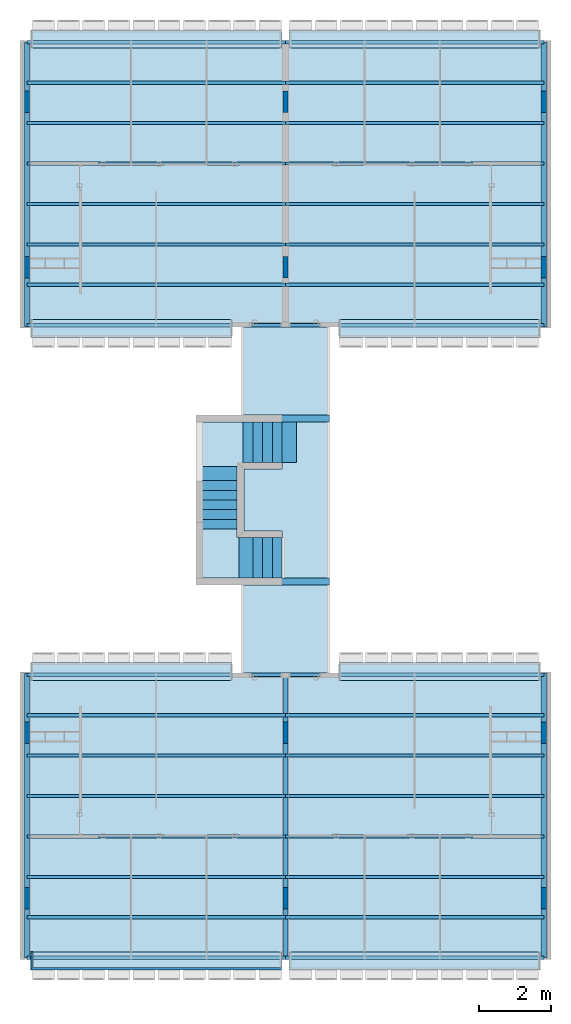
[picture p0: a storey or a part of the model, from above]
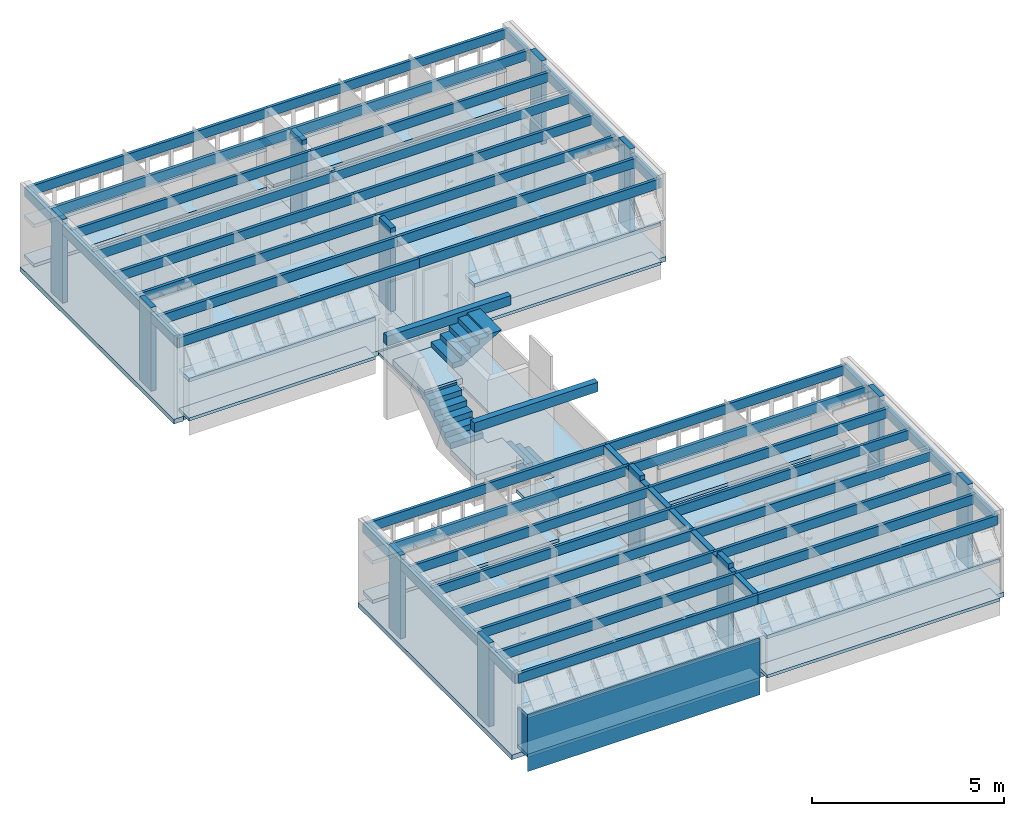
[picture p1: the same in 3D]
Properties of the parts of a building model (IFC2X3), part 1 of 3

# File
Description: ViewDefinition [CoordinationView_V2.0], ExchangeRequirement [Architecture], Option [IfcExportBaseQuantities: Off], Option [IfcExportElementOnOffAndFrozenLayers: On], Option [IfcExplodeExternalReferences: Off], Option [IfcTesselateBSplineCurvesAndSurfaces: Off], Option [IfcExportSweptSolidAsBRep: Off], Option [IfcExportProfileCenterOfGravity: Off], Option [IfcExportMultiPlyElementsAsAggregated: Off], Option [IfcExportTesselation: 0.000000], Option [IfcCreateUniqueGuidForBlocks: On], Option [IfcCreateUniqueGuidForXrefs: On]
File name: C:\\Users\\Marcelo\\Documents\\FAU\\_LabBIM 2021 2022\\_Servidor Modelos FAU\\Tadashi-Cecap-Archicad\\CECAP-PMR R06 IFC2X3 pav2 bricscad.ifc
Time: 2024-07-12T12:13:49
Author: Undefined
Organization: Undefined
Written by: BricsCAD BIM 24.2.06
Made in: BricsCAD BIM 24.2.06
Authorization: Undefined

# IfcSite, Site
RefLatitude: -23, -32, 0, 0; RefLongitude: -46, -38, 0, 0; RefElevation: 0 mm

# IfcBuilding, Construção
ElevationOfRefHeight: 0 mm; ElevationOfTerrain: 0 mm

# IfcBuildingStorey, Segundo Pavimento
In: Construção
Elevation: 2650 mm

# IfcSpace: CIRCULAÇÃO (2)
In: Segundo Pavimento
AC_Equantity_Selo_de_Zona_01_25 - Perímetro dos Vãos: 0; Largura Combinada das Janelas: 0; Nível do Piso: 0; Espessura do Subpiso: 0; Tamanho de Fonte para Texto de Detalhe (modelo): 300
AC_Pset_RenovationAndPhasing - Renovation Status: Existing
ArchiCADQuantities - Elevação à Origem do Projeto: 2650; Elevação ao 1º Nível de Referência: 2650; Elevação ao 2º Nível de Referência: 2650; Elevação ao Nível do Mar: 2650; Elevação ao Piso: 0; Afastamento da Origem: 0; Elevação da Base Ao Primeiro Nível de Referência: 2650; Elevação da Base Ao Piso de Origem: 0; Elevação da Base À Cota Zero: 2650; Elevação da Base Ao Nível do Mar: 2650; Elevação da Base Ao Segundo Nível de Referência: 2650; Afastamento do Topo: 0; Número de Janelas: 0; Número de Pilares: 0; Perímetro Furos da Planta: 0; Nível Base: 0; Número de Luminárias: 0; Número de Objetos: 0; Área de Superfície das Janelas: 0; Largura Janelas: 0; Espessura de Pavimento: 0; Redução de área: 1; Extrair Área da Base do Pilar: 0; Extrair Área da Trama: 0; Área Baixa Extraída: 0; Extrair Área da Base da Parede: 0; Área Total Extraída: 0; Inserção da Parede no Lado Posterior da Área de Superfície: 0; Inserção da Parede no Lado da Área de Superfície: 0; Inserção da Parede na Área da Superfície do Topo: 0; Área Extraída da Parede Cortina: 0
BaseQuantities - FinishFloorHeight: 0
ILUMINAÇÃO E VENTILAÇÃO (Expressão) - Área das Aberturas Projetada: 0; Atende: Atende; Não Atende: Não Atende
REVESTIMENTO DE PAREDE POR ZONA (Expressão) - Número de Linhas: 10; DImensão 1: 0; Dimensão 2: 0; Largura do Rejunte: 10; Altura do Revestimento: 100
RODAPÉ (Expressão) - Comprimento da Barra (m): 2.4; Custo da Barra: 0; Estimativa de Custo: 0
Name | LongName | Classification | Perímetro = Perímetro Útil = Perímetro Útil da Zona = Perímetro Bruto Zona = GrossPerimeter = NetPerimeter | Comprimento das Paredes Perímetro = Perímetro Paredes | Largura Combinada das Portas = Largura Portas | Altura-2 = Altura = Elevação do Topo Ao Piso de Origem = Height = FinishCeilingHeight = ClearHeight | Área = Área da Superfície do Topo (Líquida) = Área da Superfície da Base (Líquida) = Área Calculada = Área Medida = Área Líquida Medida = Área Reduzida = GrossFloorArea = NetFloorArea = SpaceNetFloorAreaBOMA = SpaceUsableFloorAreaBOMA = GrossCeilingArea = NetCeilingArea | Volume (Líquido) = GrossVolume = NetVolume | Elevação do Topo ao Primeiro Nível de Referência = Elevação do Topo À Cota Zero = Elevação do Topo Ao Nível do Mar = Elevação do Topo Ao Segundo Nível de Referência | Área da Superfície da Borda (Líquida) | Número de Portas | Número de Vigas | Número de Itens de Paredes | Área de Superfície das Portas | Área de Superfície das Paredes = NetWallArea | Número dos Cantos Côncavos | Número de Cantos | GrossWallArea | ID Dinâmico por Classificação | Zona - Número de Azulejos Necessários | Quantidade de Barras | Estimativa de Rodapé (ml)
33 | CORREDOR | Zoneamento (Classificação ARCHICAD); 4A 16 04 01 Corredor (NBR 15965-6 4A) | 28680 | 26812.9 | 3600 | 2650 | 20.0698 | 53.185 | 5300 | 76.002 | 4 | 6 | 23 | 7.56 | 34.421 | 10 | 24 | 41.981 | Zoneamento -032 | 25080 | 10 | 23212.9
34 | ESCADA | Zoneamento (Classificação ARCHICAD); 4A 16 01 04 07 Escada de Uso Comum (NBR 15965-6 4A) | 15630 | 9050 | 0 | 5300 | 7.0315 | 37.2669 | 7950 | 41.4195 | 0 | 2 | 6 | 0 | 23.0336 | 2 | 8 | 23.0336 | Zoneamento -031 | 15630 | 4 | 9050

# IfcSpace: ÁREA PRIVATIVA APTO 05 (7)
In: Segundo Pavimento
AC_Equantity_Selo_de_Zona_01_25 - Perímetro dos Vãos: 0; Nível do Piso: 0; Espessura do Subpiso: 0; Altura-2: 2650; Tamanho de Fonte para Texto de Detalhe (modelo): 300
AC_Pset_RenovationAndPhasing - Renovation Status: Existing
ArchiCADQuantities - Altura: 2650; Elevação à Origem do Projeto: 2650; Elevação ao 1º Nível de Referência: 2650; Elevação ao 2º Nível de Referência: 2650; Elevação ao Nível do Mar: 2650; Elevação ao Piso: 0; Afastamento da Origem: 0; Elevação do Topo ao Primeiro Nível de Referência: 5300; Elevação do Topo Ao Piso de Origem: 2650; Elevação do Topo À Cota Zero: 5300; Elevação do Topo Ao Nível do Mar: 5300; Elevação do Topo Ao Segundo Nível de Referência: 5300; Elevação da Base Ao Primeiro Nível de Referência: 2650; Elevação da Base Ao Piso de Origem: 0; Elevação da Base À Cota Zero: 2650; Elevação da Base Ao Nível do Mar: 2650; Elevação da Base Ao Segundo Nível de Referência: 2650; Afastamento do Topo: 0; Número de Janelas: 0; Número de Pilares: 0; Perímetro Furos da Planta: 0; Nível Base: 0; Número de Luminárias: 0; Número de Objetos: 0; Área de Superfície das Janelas: 0; Largura Janelas: 0; Espessura de Pavimento: 0; Redução de área: 1; Extrair Área da Base do Pilar: 0; Extrair Área da Trama: 0; Área Baixa Extraída: 0; Extrair Área da Base da Parede: 0; Número dos Cantos Côncavos: 0; Número de Cantos: 4; Área Total Extraída: 0; Inserção da Parede no Lado Posterior da Área de Superfície: 0; Inserção da Parede no Lado da Área de Superfície: 0; Inserção da Parede na Área da Superfície do Topo: 0; Área Extraída da Parede Cortina: 0
BaseQuantities - Height: 2650; FinishCeilingHeight: 2650; FinishFloorHeight: 0; ClearHeight: 2650
ILUMINAÇÃO E VENTILAÇÃO (Expressão) - Área das Aberturas Projetada: 0; Atende: Atende; Não Atende: Não Atende
REVESTIMENTO DE PAREDE POR ZONA (Expressão) - Número de Linhas: 10; DImensão 1: 0; Dimensão 2: 0; Largura do Rejunte: 10; Altura do Revestimento: 100
RODAPÉ (Expressão) - Comprimento da Barra (m): 2.4; Custo da Barra: 0; Estimativa de Custo: 0
Name | LongName | Classification | Perímetro = Perímetro Útil = Perímetro Útil da Zona = Perímetro Bruto Zona = GrossPerimeter = NetPerimeter | Comprimento das Paredes Perímetro = Perímetro Paredes | Largura Combinada das Portas | Largura Combinada das Janelas | Área = Área da Superfície do Topo (Líquida) = Área da Superfície da Base (Líquida) = Área Calculada = Área Medida = Área Líquida Medida = Área Reduzida = GrossFloorArea = NetFloorArea = SpaceNetFloorAreaBOMA = SpaceUsableFloorAreaBOMA = GrossCeilingArea = NetCeilingArea | Volume (Líquido) = GrossVolume = NetVolume | Área da Superfície da Borda (Líquida) | Número de Portas | Número de Vigas | Número de Itens de Paredes | Área de Superfície das Portas | Área de Superfície das Paredes = NetWallArea | Largura Portas | GrossWallArea | ID Dinâmico por Classificação | Zona - Número de Azulejos Necessários | Quantidade de Barras | Estimativa de Rodapé (ml)
17 | LAVANDERIA | Zoneamento (Classificação ARCHICAD); 4A 19 04 04 Lavanderia (NBR 15965-6 4A) | 5940 | 3510 | 0 | 0 | 2.187 | 5.79555 | 15.741 | 0 | 2 | 3 | 0 | 9.09455 | 0 | 9.09455 | Zoneamento -025 | 5940 | 2 | 3510
09 | SALA | Zoneamento (Classificação ARCHICAD); 4A 19 01 07 Sala de Estar (NBR 15965-6 4A) | 15959.6 | 9809.78 | 710 | 2040 | 15.6592 | 41.497 | 42.2928 | 1 | 5 | 5 | 1.89 | 21.4728 | 900 | 23.3628 | Zoneamento -024 | 15060 | 4 | 8909.78
31 | QUARTO | Zoneamento (Classificação ARCHICAD); 4A 19 01 01 Dormitório (NBR 15965-6 4A) | 11010.2 | 8850.18 | 0 | 2080 | 7.12419 | 18.8791 | 29.177 | 0 | 4 | 2 | 0 | 16.794 | 0 | 16.794 | Zoneamento -028 | 11010 | 4 | 8850.18
13 | WC | Zoneamento (Classificação ARCHICAD); 4A 19 04 07 Banheiro residencial (NBR 15965-6 4A) | 7859.56 | 7859.56 | 710 | 0 | 3.4827 | 9.22916 | 20.8278 | 1 | 3 | 4 | 1.491 | 17.6449 | 710 | 19.1359 | Zoneamento -029 | 7150 | 3 | 7149.56
05 | COZINHA | Zoneamento (Classificação ARCHICAD); 4A 19 01 25 Cozinha (NBR 15965-6 4A) | 13079.6 | 9809.78 | 710 | 2040 | 9.17955 | 24.3258 | 34.6608 | 1 | 5 | 3 | 1.491 | 17.572 | 710 | 19.063 | Zoneamento -026 | 12370 | 4 | 9099.78
27 | QUARTO | Zoneamento (Classificação ARCHICAD); 4A 19 01 01 Dormitório (NBR 15965-6 4A) | 10970.4 | 8830.36 | 0 | 2060 | 7.05588 | 18.6981 | 29.0715 | 0 | 4 | 2 | 0 | 16.8413 | 0 | 16.8413 | Zoneamento -027 | 10970 | 4 | 8830.36
23 | QUARTO | Zoneamento (Classificação ARCHICAD); 4A 19 01 01 Dormitório (NBR 15965-6 4A) | 12310.4 | 11330.4 | 0 | 2780 | 9.38311 | 24.8652 | 32.6227 | 0 | 3 | 2 | 0 | 16.6677 | 0 | 16.6677 | Zoneamento -030 | 12311 | 5 | 11330.4

# IfcSpace: ÁREA PRIVATIVA APTO 06 (7)
In: Segundo Pavimento
AC_Equantity_Selo_de_Zona_01_25 - Perímetro dos Vãos: 0; Nível do Piso: 0; Espessura do Subpiso: 0; Altura-2: 2650; Tamanho de Fonte para Texto de Detalhe (modelo): 300
AC_Pset_RenovationAndPhasing - Renovation Status: Existing
ArchiCADQuantities - Altura: 2650; Elevação à Origem do Projeto: 2650; Elevação ao 1º Nível de Referência: 2650; Elevação ao 2º Nível de Referência: 2650; Elevação ao Nível do Mar: 2650; Elevação ao Piso: 0; Afastamento da Origem: 0; Elevação do Topo ao Primeiro Nível de Referência: 5300; Elevação do Topo Ao Piso de Origem: 2650; Elevação do Topo À Cota Zero: 5300; Elevação do Topo Ao Nível do Mar: 5300; Elevação do Topo Ao Segundo Nível de Referência: 5300; Elevação da Base Ao Primeiro Nível de Referência: 2650; Elevação da Base Ao Piso de Origem: 0; Elevação da Base À Cota Zero: 2650; Elevação da Base Ao Nível do Mar: 2650; Elevação da Base Ao Segundo Nível de Referência: 2650; Afastamento do Topo: 0; Número de Janelas: 0; Número de Pilares: 0; Perímetro Furos da Planta: 0; Nível Base: 0; Número de Luminárias: 0; Número de Objetos: 0; Área de Superfície das Janelas: 0; Largura Janelas: 0; Espessura de Pavimento: 0; Redução de área: 1; Extrair Área da Base do Pilar: 0; Extrair Área da Trama: 0; Área Baixa Extraída: 0; Extrair Área da Base da Parede: 0; Número dos Cantos Côncavos: 0; Número de Cantos: 4; Área Total Extraída: 0; Inserção da Parede no Lado Posterior da Área de Superfície: 0; Inserção da Parede no Lado da Área de Superfície: 0; Inserção da Parede na Área da Superfície do Topo: 0; Área Extraída da Parede Cortina: 0
BaseQuantities - Height: 2650; FinishCeilingHeight: 2650; FinishFloorHeight: 0; ClearHeight: 2650
ILUMINAÇÃO E VENTILAÇÃO (Expressão) - Área das Aberturas Projetada: 0; Atende: Atende; Não Atende: Não Atende
REVESTIMENTO DE PAREDE POR ZONA (Expressão) - Número de Linhas: 10; DImensão 1: 0; Dimensão 2: 0; Largura do Rejunte: 10; Altura do Revestimento: 100
RODAPÉ (Expressão) - Comprimento da Barra (m): 2.4; Custo da Barra: 0; Estimativa de Custo: 0
Name | LongName | Classification | Perímetro = Perímetro Útil = Perímetro Útil da Zona = Perímetro Bruto Zona = GrossPerimeter = NetPerimeter | Comprimento das Paredes Perímetro = Perímetro Paredes | Largura Combinada das Portas | Largura Combinada das Janelas | Área = Área da Superfície do Topo (Líquida) = Área da Superfície da Base (Líquida) = Área Calculada = Área Medida = Área Líquida Medida = Área Reduzida = GrossFloorArea = NetFloorArea = SpaceNetFloorAreaBOMA = SpaceUsableFloorAreaBOMA = GrossCeilingArea = NetCeilingArea | Volume (Líquido) = GrossVolume = NetVolume | Área da Superfície da Borda (Líquida) | Número de Portas | Número de Vigas | Número de Itens de Paredes | Área de Superfície das Portas | Área de Superfície das Paredes = NetWallArea | Largura Portas | GrossWallArea | ID Dinâmico por Classificação | Zona - Número de Azulejos Necessários | Quantidade de Barras | Estimativa de Rodapé (ml)
13 | WC | Zoneamento (Classificação ARCHICAD); 4A 19 04 07 Banheiro residencial (NBR 15965-6 4A) | 7859.56 | 7859.56 | 710 | 0 | 3.4827 | 9.22916 | 20.8278 | 1 | 3 | 4 | 1.491 | 17.6449 | 710 | 19.1359 | Zoneamento -015 | 7150 | 3 | 7149.56
23 | QUARTO | Zoneamento (Classificação ARCHICAD); 4A 19 01 01 Dormitório (NBR 15965-6 4A) | 12310.4 | 11330.4 | 0 | 2780 | 9.38311 | 24.8652 | 32.6227 | 0 | 3 | 2 | 0 | 16.6677 | 0 | 16.6677 | Zoneamento -014 | 12311 | 5 | 11330.4
05 | COZINHA | Zoneamento (Classificação ARCHICAD); 4A 19 01 25 Cozinha (NBR 15965-6 4A) | 13079.6 | 9809.78 | 710 | 2040 | 9.17955 | 24.3258 | 34.6608 | 1 | 5 | 3 | 1.491 | 17.572 | 710 | 19.063 | Zoneamento -016 | 12370 | 4 | 9099.78
09 | SALA | Zoneamento (Classificação ARCHICAD); 4A 19 01 07 Sala de Estar (NBR 15965-6 4A) | 15959.6 | 9809.78 | 710 | 2040 | 15.6592 | 41.497 | 42.2928 | 1 | 5 | 5 | 1.89 | 21.4728 | 900 | 23.3628 | Zoneamento -017 | 15060 | 4 | 8909.78
17 | LAVANDERIA | Zoneamento (Classificação ARCHICAD); 4A 19 04 04 Lavanderia (NBR 15965-6 4A) | 5940 | 3510 | 0 | 0 | 2.187 | 5.79555 | 15.741 | 0 | 2 | 3 | 0 | 9.09455 | 0 | 9.09455 | Zoneamento -035 | 5940 | 2 | 3510
27 | QUARTO | Zoneamento (Classificação ARCHICAD); 4A 19 01 01 Dormitório (NBR 15965-6 4A) | 10970.4 | 8830.36 | 0 | 2060 | 7.05588 | 18.6981 | 29.0715 | 0 | 4 | 2 | 0 | 16.8413 | 0 | 16.8413 | Zoneamento -034 | 10970 | 4 | 8830.36
31 | QUARTO | Zoneamento (Classificação ARCHICAD); 4A 19 01 01 Dormitório (NBR 15965-6 4A) | 11010.2 | 8850.18 | 0 | 2080 | 7.12419 | 18.8791 | 29.177 | 0 | 4 | 2 | 0 | 16.794 | 0 | 16.794 | Zoneamento -033 | 11010 | 4 | 8850.18

# IfcSpace: ÁREA PRIVATIVA APTO 07 (7)
In: Segundo Pavimento
AC_Equantity_Selo_de_Zona_01_25 - Perímetro dos Vãos: 0; Nível do Piso: 0; Espessura do Subpiso: 0; Altura-2: 2650; Tamanho de Fonte para Texto de Detalhe (modelo): 300
AC_Pset_RenovationAndPhasing - Renovation Status: Existing
ArchiCADQuantities - Altura: 2650; Elevação à Origem do Projeto: 2650; Elevação ao 1º Nível de Referência: 2650; Elevação ao 2º Nível de Referência: 2650; Elevação ao Nível do Mar: 2650; Elevação ao Piso: 0; Afastamento da Origem: 0; Elevação do Topo ao Primeiro Nível de Referência: 5300; Elevação do Topo Ao Piso de Origem: 2650; Elevação do Topo À Cota Zero: 5300; Elevação do Topo Ao Nível do Mar: 5300; Elevação do Topo Ao Segundo Nível de Referência: 5300; Elevação da Base Ao Primeiro Nível de Referência: 2650; Elevação da Base Ao Piso de Origem: 0; Elevação da Base À Cota Zero: 2650; Elevação da Base Ao Nível do Mar: 2650; Elevação da Base Ao Segundo Nível de Referência: 2650; Afastamento do Topo: 0; Número de Janelas: 0; Número de Pilares: 0; Perímetro Furos da Planta: 0; Nível Base: 0; Número de Luminárias: 0; Número de Objetos: 0; Área de Superfície das Janelas: 0; Largura Janelas: 0; Espessura de Pavimento: 0; Redução de área: 1; Extrair Área da Base do Pilar: 0; Extrair Área da Trama: 0; Área Baixa Extraída: 0; Extrair Área da Base da Parede: 0; Número dos Cantos Côncavos: 0; Número de Cantos: 4; Área Total Extraída: 0; Inserção da Parede no Lado Posterior da Área de Superfície: 0; Inserção da Parede no Lado da Área de Superfície: 0; Inserção da Parede na Área da Superfície do Topo: 0; Área Extraída da Parede Cortina: 0
BaseQuantities - Height: 2650; FinishCeilingHeight: 2650; FinishFloorHeight: 0; ClearHeight: 2650
ILUMINAÇÃO E VENTILAÇÃO (Expressão) - Área das Aberturas Projetada: 0; Atende: Atende; Não Atende: Não Atende
REVESTIMENTO DE PAREDE POR ZONA (Expressão) - Número de Linhas: 10; DImensão 1: 0; Dimensão 2: 0; Largura do Rejunte: 10; Altura do Revestimento: 100
RODAPÉ (Expressão) - Comprimento da Barra (m): 2.4; Custo da Barra: 0; Estimativa de Custo: 0
Name | LongName | Classification | Perímetro = Perímetro Útil = Perímetro Útil da Zona = Perímetro Bruto Zona = GrossPerimeter = NetPerimeter | Comprimento das Paredes Perímetro = Perímetro Paredes | Largura Combinada das Portas | Largura Combinada das Janelas | Área = Área da Superfície do Topo (Líquida) = Área da Superfície da Base (Líquida) = Área Calculada = Área Medida = Área Líquida Medida = Área Reduzida = GrossFloorArea = NetFloorArea = SpaceNetFloorAreaBOMA = SpaceUsableFloorAreaBOMA = GrossCeilingArea = NetCeilingArea | Volume (Líquido) = GrossVolume = NetVolume | Área da Superfície da Borda (Líquida) | Número de Portas | Número de Vigas | Número de Itens de Paredes | Área de Superfície das Portas | Área de Superfície das Paredes = NetWallArea | Largura Portas | GrossWallArea | ID Dinâmico por Classificação | Zona - Número de Azulejos Necessários | Quantidade de Barras | Estimativa de Rodapé (ml)
13 | WC | Zoneamento (Classificação ARCHICAD); 4A 19 04 07 Banheiro residencial (NBR 15965-6 4A) | 7859.56 | 7859.56 | 710 | 0 | 3.4827 | 9.22916 | 20.8278 | 1 | 3 | 4 | 1.491 | 17.6449 | 710 | 19.1359 | Zoneamento -019 | 7150 | 3 | 7149.56
05 | COZINHA | Zoneamento (Classificação ARCHICAD); 4A 19 01 25 Cozinha (NBR 15965-6 4A) | 13079.6 | 9809.78 | 710 | 2040 | 9.17955 | 24.3258 | 34.6608 | 1 | 5 | 3 | 1.491 | 17.572 | 710 | 19.063 | Zoneamento -022 | 12370 | 4 | 9099.78
09 | SALA | Zoneamento (Classificação ARCHICAD); 4A 19 01 07 Sala de Estar (NBR 15965-6 4A) | 15959.6 | 9809.78 | 710 | 2040 | 15.6592 | 41.497 | 42.2928 | 1 | 5 | 5 | 1.89 | 21.5955 | 900 | 23.4855 | Zoneamento -013 | 15060 | 4 | 8909.78
27 | QUARTO | Zoneamento (Classificação ARCHICAD); 4A 19 01 01 Dormitório (NBR 15965-6 4A) | 10970.4 | 8830.36 | 0 | 2060 | 7.05588 | 18.6981 | 29.0715 | 0 | 4 | 2 | 0 | 16.8413 | 0 | 16.8413 | Zoneamento -021 | 10970 | 4 | 8830.36
31 | QUARTO | Zoneamento (Classificação ARCHICAD); 4A 19 01 01 Dormitório (NBR 15965-6 4A) | 11010.2 | 8850.18 | 0 | 2080 | 7.12419 | 18.8791 | 29.177 | 0 | 4 | 2 | 0 | 16.8871 | 0 | 16.8871 | Zoneamento -020 | 11010 | 4 | 8850.18
17 | LAVANDERIA | Zoneamento (Classificação ARCHICAD); 4A 19 04 04 Lavanderia (NBR 15965-6 4A) | 5940 | 3510 | 0 | 0 | 2.187 | 5.79555 | 15.741 | 0 | 2 | 3 | 0 | 9.09455 | 0 | 9.09455 | Zoneamento -023 | 5940 | 2 | 3510
23 | QUARTO | Zoneamento (Classificação ARCHICAD); 4A 19 01 01 Dormitório (NBR 15965-6 4A) | 12310.4 | 11330.4 | 0 | 2780 | 9.38311 | 24.8652 | 32.6227 | 0 | 3 | 2 | 0 | 16.6677 | 0 | 16.6677 | Zoneamento -018 | 12311 | 5 | 11330.4

# IfcSpace: ÁREA PRIVATIVA APTO 08 (7)
In: Segundo Pavimento
AC_Equantity_Selo_de_Zona_01_25 - Perímetro dos Vãos: 0; Nível do Piso: 0; Espessura do Subpiso: 0; Altura-2: 2650; Tamanho de Fonte para Texto de Detalhe (modelo): 300
AC_Pset_RenovationAndPhasing - Renovation Status: Existing
ArchiCADQuantities - Altura: 2650; Elevação à Origem do Projeto: 2650; Elevação ao 1º Nível de Referência: 2650; Elevação ao 2º Nível de Referência: 2650; Elevação ao Nível do Mar: 2650; Elevação ao Piso: 0; Afastamento da Origem: 0; Elevação do Topo ao Primeiro Nível de Referência: 5300; Elevação do Topo Ao Piso de Origem: 2650; Elevação do Topo À Cota Zero: 5300; Elevação do Topo Ao Nível do Mar: 5300; Elevação do Topo Ao Segundo Nível de Referência: 5300; Elevação da Base Ao Primeiro Nível de Referência: 2650; Elevação da Base Ao Piso de Origem: 0; Elevação da Base À Cota Zero: 2650; Elevação da Base Ao Nível do Mar: 2650; Elevação da Base Ao Segundo Nível de Referência: 2650; Afastamento do Topo: 0; Número de Janelas: 0; Número de Pilares: 0; Perímetro Furos da Planta: 0; Nível Base: 0; Número de Luminárias: 0; Número de Objetos: 0; Área de Superfície das Janelas: 0; Largura Janelas: 0; Espessura de Pavimento: 0; Redução de área: 1; Extrair Área da Base do Pilar: 0; Extrair Área da Trama: 0; Área Baixa Extraída: 0; Extrair Área da Base da Parede: 0; Número dos Cantos Côncavos: 0; Número de Cantos: 4; Área Total Extraída: 0; Inserção da Parede no Lado Posterior da Área de Superfície: 0; Inserção da Parede no Lado da Área de Superfície: 0; Inserção da Parede na Área da Superfície do Topo: 0; Área Extraída da Parede Cortina: 0
BaseQuantities - Height: 2650; FinishCeilingHeight: 2650; FinishFloorHeight: 0; ClearHeight: 2650
ILUMINAÇÃO E VENTILAÇÃO (Expressão) - Área das Aberturas Projetada: 0; Atende: Atende; Não Atende: Não Atende
REVESTIMENTO DE PAREDE POR ZONA (Expressão) - Número de Linhas: 10; DImensão 1: 0; Dimensão 2: 0; Largura do Rejunte: 10; Altura do Revestimento: 100
RODAPÉ (Expressão) - Comprimento da Barra (m): 2.4; Custo da Barra: 0; Estimativa de Custo: 0
Name | LongName | Classification | Perímetro = Perímetro Útil = Perímetro Útil da Zona = Perímetro Bruto Zona = GrossPerimeter = NetPerimeter | Comprimento das Paredes Perímetro = Perímetro Paredes | Largura Combinada das Portas | Largura Combinada das Janelas | Área = Área da Superfície do Topo (Líquida) = Área da Superfície da Base (Líquida) = Área Calculada = Área Medida = Área Líquida Medida = Área Reduzida = GrossFloorArea = NetFloorArea = SpaceNetFloorAreaBOMA = SpaceUsableFloorAreaBOMA = GrossCeilingArea = NetCeilingArea | Volume (Líquido) = GrossVolume = NetVolume | Área da Superfície da Borda (Líquida) | Número de Portas | Número de Vigas | Número de Itens de Paredes | Área de Superfície das Portas | Área de Superfície das Paredes = NetWallArea | Largura Portas | GrossWallArea | ID Dinâmico por Classificação | Zona - Número de Azulejos Necessários | Quantidade de Barras | Estimativa de Rodapé (ml)
31 | QUARTO | Zoneamento (Classificação ARCHICAD); 4A 19 01 01 Dormitório (NBR 15965-6 4A) | 11010.2 | 8850.18 | 0 | 2080 | 7.12419 | 18.8791 | 29.177 | 0 | 4 | 2 | 0 | 16.8871 | 0 | 16.8871 | Zoneamento -009 | 11010 | 4 | 8850.18
27 | QUARTO | Zoneamento (Classificação ARCHICAD); 4A 19 01 01 Dormitório (NBR 15965-6 4A) | 10970.4 | 8830.36 | 0 | 2060 | 7.05588 | 18.6981 | 29.0715 | 0 | 4 | 2 | 0 | 16.8413 | 0 | 16.8413 | Zoneamento -008 | 10970 | 4 | 8830.36
17 | LAVANDERIA | Zoneamento (Classificação ARCHICAD); 4A 19 04 04 Lavanderia (NBR 15965-6 4A) | 5940 | 3510 | 0 | 0 | 2.187 | 5.79555 | 15.741 | 0 | 2 | 3 | 0 | 9.09455 | 0 | 9.09455 | Zoneamento -007 | 5940 | 2 | 3510
23 | QUARTO | Zoneamento (Classificação ARCHICAD); 4A 19 01 01 Dormitório (NBR 15965-6 4A) | 12310.4 | 11330.4 | 0 | 2780 | 9.38311 | 24.8652 | 32.6227 | 0 | 3 | 2 | 0 | 16.6677 | 0 | 16.6677 | Zoneamento -012 | 12311 | 5 | 11330.4
13 | WC | Zoneamento (Classificação ARCHICAD); 4A 19 04 07 Banheiro residencial (NBR 15965-6 4A) | 7859.56 | 7859.56 | 710 | 0 | 3.4827 | 9.22916 | 20.8278 | 1 | 3 | 4 | 1.491 | 17.6449 | 710 | 19.1359 | Zoneamento -011 | 7150 | 3 | 7149.56
09 | SALA | Zoneamento (Classificação ARCHICAD); 4A 19 01 07 Sala de Estar (NBR 15965-6 4A) | 15959.6 | 9809.78 | 710 | 2040 | 15.6592 | 41.497 | 42.2928 | 1 | 5 | 5 | 1.89 | 21.5955 | 900 | 23.4855 | Zoneamento -010 | 15060 | 4 | 8909.78
05 | COZINHA | Zoneamento (Classificação ARCHICAD); 4A 19 01 25 Cozinha (NBR 15965-6 4A) | 13079.6 | 9809.78 | 710 | 2040 | 9.17955 | 24.3258 | 34.6608 | 1 | 5 | 3 | 1.491 | 17.572 | 710 | 19.063 | Zoneamento -006 | 12370 | 4 | 9099.78

# IfcBeam: Concreto Armado Moldado in Loco - Estrutural 150 x 300 (5)
In: Segundo Pavimento
Classification: Viga (Classificação ARCHICAD); 3E 12 06 02 00 Viga (NBR 15965-5 3E); Material: Concreto Armado Moldado in Loco - Estrutural
AC_Pset_RenovationAndPhasing - Renovation Status: Existing
ArchiCADQuantities - Área: 1.00275; Altura: 300; Volume (Líquido): 0.300824; Largura: 150; Elevação à Origem do Projeto: 5150; Elevação ao 1º Nível de Referência: 5150; Elevação ao 2º Nível de Referência: 5150; Elevação ao Nível do Mar: 5150; Elevação ao Piso: 2500; Afastamento da Origem: 2500; Área da Superfície: 6.31348; Comprimento 3D: 6729.98; Volume (Condicional): 0.300824; Volume (Bruto): 0.356849; Elevação do Topo ao Primeiro Nível de Referência: 5150; Elevação do Topo Ao Piso de Origem: 2500; Elevação do Topo À Cota Zero: 5150; Elevação do Topo Ao Nível do Mar: 5150; Elevação do Topo Ao Segundo Nível de Referência: 5150; Elevação da Base Ao Primeiro Nível de Referência: 4850; Elevação da Base Ao Piso de Origem: 2200; Elevação da Base À Cota Zero: 4850; Elevação da Base Ao Nível do Mar: 4850; Elevação da Base Ao Segundo Nível de Referência: 4850; Altura do Corte Transversal no Topo/Terminação (perpendicular): 300; Altura do Corte Transversal na Base/Início (perpendicular): 300; Largura do Corte Transversal no Topo/Terminação (perpendicular): 150; Largura do Corte Transversal na Base/Início (perpendicular): 150; Altura do Corte Transversal no Topo/Terminação (corte): 300; Altura do Corte Transversal na Base/Início (corte): 300; Largura do Corte Transversal no Topo/Terminação (corte): 150; Largura do Corte Transversal na Base/Início (corte): 150; Área do Corte Transversal na Base/Início: 0.0225; Altura do Corte Transversal no Topo/Terminação: 0.045; Número de Segmentos: 1; Área da Superfície do Topo (Líquida): 1.00275; Área da Superfície da Base (Líquida): 1.00275; Área da Superfície das Extremidades da Viga: 0.0675; Número Furo: 0; Área da Borda do Furo: 0; Área de Superfície dos Furos: 0; Volume Furos: 0; Comprimento Esquerda: 7929.98; Comprimento Direita: 7929.98; Afastamento Eixo a partir do Centro: 0
BaseQuantities - NetSurfaceAreaExtrudedSides: 6.01648; Length: 6729.98; Width: 150; Depth: 300; CrossSectionArea: 0.045; OuterSurfaceArea: 6.01648; TotalSurfaceArea: 6.10648; GrossSurfaceArea: 6.10648; GrossVolume: 0.356849; NetSurfaceArea: 6.10648; NetVolume: 0.300824
ESTRUTURA (Expressão) - Custo por Volume (m3): 0; Estimativa de Custo Total por Volume: 0; Estimativa de Custo Total por Volume (R$): 0,00 R$
SUPERFÍCIES (Mapas) - Superfície do Topo (Geral): Concreto - 03; Superfície da Base (Geral): Concreto - 03; Área da Superfície do Topo (Geral): 1.00275; Área da Superfície da Base (Geral): 1.00275
Pset_BeamCommon - Reference: Concreto Armado Moldado in Loco - Estrutural 150 x 300; LoadBearing: yes
Name | Área da Superfície do Lado Esquerdo da Viga (Líquida) | Área da Superfície do Lado Direito da Viga (Líquida) | ID Dinâmico por Classificação | IsExternal
APTO5-VIGA-009 | 1.99199 | 2.01899 | Viga -009 | yes
APTO6-VIGA-009 | 2.01899 | 1.99199 | Viga -009 | yes
APTO7-VIGA-009 | 2.01899 | 1.99199 | Viga -009 | yes
APTO8-VIGA-009 | 1.99199 | 2.01899 | Viga -009 | yes
CIRC2-VIGA-012 | 1.99199 | 2.01899 | Viga -012 | no

# IfcBeam: Concreto Armado Moldado in Loco - Estrutural 190 x 300 (2)
In: Segundo Pavimento
Classification: Viga (Classificação ARCHICAD); 3E 12 06 02 00 Viga (NBR 15965-5 3E); Material: Concreto Armado Moldado in Loco - Estrutural
AC_Pset_RenovationAndPhasing - Renovation Status: Existing
ArchiCADQuantities - Área: 0.7068; Altura: 300; Volume (Líquido): 0.21204; Largura: 190; Elevação à Origem do Projeto: 5000; Elevação ao 1º Nível de Referência: 5000; Elevação ao 2º Nível de Referência: 5000; Elevação ao Nível do Mar: 5000; Elevação ao Piso: 2350; Afastamento da Origem: 2350; Área da Superfície: 3.7596; Comprimento 3D: 3720; Volume (Condicional): 0.21204; Volume (Bruto): 0.21204; Elevação do Topo ao Primeiro Nível de Referência: 5150; Elevação do Topo Ao Piso de Origem: 2500; Elevação do Topo À Cota Zero: 5150; Elevação do Topo Ao Nível do Mar: 5150; Elevação do Topo Ao Segundo Nível de Referência: 5150; Elevação da Base Ao Primeiro Nível de Referência: 4850; Elevação da Base Ao Piso de Origem: 2200; Elevação da Base À Cota Zero: 4850; Elevação da Base Ao Nível do Mar: 4850; Elevação da Base Ao Segundo Nível de Referência: 4850; Altura do Corte Transversal no Topo/Terminação (perpendicular): 300; Altura do Corte Transversal na Base/Início (perpendicular): 300; Largura do Corte Transversal no Topo/Terminação (perpendicular): 190; Largura do Corte Transversal na Base/Início (perpendicular): 190; Altura do Corte Transversal no Topo/Terminação (corte): 300; Altura do Corte Transversal na Base/Início (corte): 300; Largura do Corte Transversal no Topo/Terminação (corte): 190; Largura do Corte Transversal na Base/Início (corte): 190; Área do Corte Transversal na Base/Início: 0.057; Altura do Corte Transversal no Topo/Terminação: 0.057; Número de Segmentos: 1; Área da Superfície do Topo (Líquida): 0.7068; Área da Superfície da Base (Líquida): 0.7068; Área da Superfície das Extremidades da Viga: 0.114; Número Furo: 0; Área da Borda do Furo: 0; Área de Superfície dos Furos: 0; Volume Furos: 0; Área da Superfície do Lado Esquerdo da Viga (Líquida): 1.116; Comprimento Esquerda: 3720; Comprimento Direita: 3720; Afastamento Eixo a partir do Centro: 0; Área da Superfície do Lado Direito da Viga (Líquida): 1.116
BaseQuantities - NetSurfaceAreaExtrudedSides: 3.6456; Length: 3720; Width: 190; Depth: 300; CrossSectionArea: 0.057; OuterSurfaceArea: 3.6456; TotalSurfaceArea: 3.7596; GrossSurfaceArea: 3.7596; GrossVolume: 0.21204; NetSurfaceArea: 3.7596; NetVolume: 0.21204
ESTRUTURA (Expressão) - Custo por Volume (m3): 0; Estimativa de Custo Total por Volume: 0; Estimativa de Custo Total por Volume (R$): 0,00 R$
SUPERFÍCIES (Mapas) - Superfície do Topo (Geral): Concreto - 03; Superfície da Base (Geral): Concreto - 03; Área da Superfície do Topo (Geral): 0.7068; Área da Superfície da Base (Geral): 0.7068
Pset_BeamCommon - Reference: Concreto Armado Moldado in Loco - Estrutural 190 x 300; IsExternal: yes; LoadBearing: yes
Name | ID Dinâmico por Classificação
CIRC2-VIGA-010 | Viga -010
CIRC2-VIGA-011 | Viga -011

# IfcBeam: Concreto Armado Moldado in Loco - Estrutural 90 x 300 (32)
In: Segundo Pavimento
Classification: Viga (Classificação ARCHICAD); 3E 12 06 02 00 Viga (NBR 15965-5 3E); Material: Concreto Armado Moldado in Loco - Estrutural
AC_Pset_RenovationAndPhasing - Renovation Status: Existing
ArchiCADQuantities - Altura: 300; Largura: 90; Elevação à Origem do Projeto: 5150; Elevação ao 1º Nível de Referência: 5150; Elevação ao 2º Nível de Referência: 5150; Elevação ao Nível do Mar: 5150; Elevação ao Piso: 2500; Afastamento da Origem: 2500; Volume (Bruto): 0.19413; Elevação do Topo ao Primeiro Nível de Referência: 5150; Elevação do Topo Ao Piso de Origem: 2500; Elevação do Topo À Cota Zero: 5150; Elevação do Topo Ao Nível do Mar: 5150; Elevação do Topo Ao Segundo Nível de Referência: 5150; Elevação da Base Ao Primeiro Nível de Referência: 4850; Elevação da Base Ao Piso de Origem: 2200; Elevação da Base À Cota Zero: 4850; Elevação da Base Ao Nível do Mar: 4850; Elevação da Base Ao Segundo Nível de Referência: 4850; Altura do Corte Transversal no Topo/Terminação (perpendicular): 300; Altura do Corte Transversal na Base/Início (perpendicular): 300; Largura do Corte Transversal no Topo/Terminação (perpendicular): 90; Largura do Corte Transversal na Base/Início (perpendicular): 90; Altura do Corte Transversal no Topo/Terminação (corte): 300; Altura do Corte Transversal na Base/Início (corte): 300; Largura do Corte Transversal no Topo/Terminação (corte): 90; Largura do Corte Transversal na Base/Início (corte): 90; Número de Segmentos: 1; Número Furo: 0; Área da Borda do Furo: 0; Área de Superfície dos Furos: 0; Volume Furos: 0; Comprimento Esquerda: 7190; Comprimento Direita: 7190; Afastamento Eixo a partir do Centro: 0
BaseQuantities - Width: 90; Depth: 300; CrossSectionArea: 0.027; GrossVolume: 0.19413
ESTRUTURA (Expressão) - Custo por Volume (m3): 0; Estimativa de Custo Total por Volume: 0; Estimativa de Custo Total por Volume (R$): 0,00 R$
SUPERFÍCIES (Mapas) - Superfície do Topo (Geral): Concreto - 03; Superfície da Base (Geral): Concreto - 03
Pset_BeamCommon - Reference: Concreto Armado Moldado in Loco - Estrutural 90 x 300; LoadBearing: yes
Name | Área = Área da Superfície do Topo (Líquida) = Área da Superfície da Base (Líquida) = Área da Superfície do Topo (Geral) = Área da Superfície da Base (Geral) | Volume (Líquido) = Volume (Condicional) = NetVolume | Área da Superfície | Comprimento 3D = Length | Área do Corte Transversal na Base/Início | Altura do Corte Transversal no Topo/Terminação | Área da Superfície das Extremidades da Viga | Área da Superfície do Lado Esquerdo da Viga (Líquida) | Área da Superfície do Lado Direito da Viga (Líquida) | NetSurfaceAreaExtrudedSides = OuterSurfaceArea | TotalSurfaceArea = GrossSurfaceArea = NetSurfaceArea | ID Dinâmico por Classificação | IsExternal
APTO5-VIGA-001 | 0.638853 | 0.191656 | 5.64571 | 7190 | 0.0105063 | 0.0105063 | 0.0210126 | 2.112 | 2.157 | 5.54671 | 5.60071 | Viga -001 | yes
APTO5-VIGA-002 | 0.6336 | 0.19008 | 5.5452 | 7040 | 0 | 0 | 0 | 2.112 | 2.112 | 5.4912 | 5.5452 | Viga -002 | no
APTO5-VIGA-003 | 0.6336 | 0.19008 | 5.5452 | 7040 | 0 | 0 | 0 | 2.112 | 2.112 | 5.4912 | 5.5452 | Viga -003 | no
APTO5-VIGA-004 | 0.6336 | 0.19008 | 5.5452 | 7040 | 0 | 0 | 0 | 2.112 | 2.112 | 5.4912 | 5.5452 | Viga -004 | no
APTO5-VIGA-005 | 0.6336 | 0.19008 | 5.5452 | 7040 | 0 | 0 | 0 | 2.112 | 2.112 | 5.4912 | 5.5452 | Viga -005 | no
APTO5-VIGA-008 | 0.64035 | 0.192105 | 5.6037 | 7115 | 0.027 | 0 | 0.027 | 2.1345 | 2.1345 | 5.5497 | 5.6037 | Viga -008 | yes
APTO5-VIGA-006 | 0.6336 | 0.19008 | 5.5452 | 7040 | 0 | 0 | 0 | 2.112 | 2.112 | 5.4912 | 5.5452 | Viga -006 | no
APTO5-VIGA-007 | 0.6336 | 0.19008 | 5.5452 | 7040 | 0 | 0 | 0 | 2.112 | 2.112 | 5.4912 | 5.5452 | Viga -007 | no
APTO6-VIGA-001 | 0.638853 | 0.191656 | 5.64571 | 7190 | 0.0105063 | 0.0105063 | 0.0210126 | 2.157 | 2.112 | 5.54671 | 5.60071 | Viga -001 | yes
APTO6-VIGA-002 | 0.6336 | 0.19008 | 5.5452 | 7040 | 0 | 0 | 0 | 2.112 | 2.112 | 5.4912 | 5.5452 | Viga -002 | no
APTO6-VIGA-003 | 0.6336 | 0.19008 | 5.5452 | 7040 | 0 | 0 | 0 | 2.112 | 2.112 | 5.4912 | 5.5452 | Viga -003 | no
APTO6-VIGA-004 | 0.6336 | 0.19008 | 5.5452 | 7040 | 0 | 0 | 0 | 2.112 | 2.112 | 5.4912 | 5.5452 | Viga -004 | no
APTO6-VIGA-005 | 0.6336 | 0.19008 | 5.5452 | 7040 | 0 | 0 | 0 | 2.112 | 2.112 | 5.4912 | 5.5452 | Viga -005 | no
APTO6-VIGA-008 | 0.6471 | 0.19413 | 5.6622 | 7190 | 0.027 | 0.027 | 0.054 | 2.157 | 2.157 | 5.6082 | 5.6622 | Viga -008 | yes
APTO6-VIGA-006 | 0.6336 | 0.19008 | 5.5452 | 7040 | 0 | 0 | 0 | 2.112 | 2.112 | 5.4912 | 5.5452 | Viga -006 | no
APTO6-VIGA-007 | 0.6336 | 0.19008 | 5.5452 | 7040 | 0 | 0 | 0 | 2.112 | 2.112 | 5.4912 | 5.5452 | Viga -007 | no
APTO7-VIGA-001 | 0.642977 | 0.192893 | 5.65395 | 7190 | 0.0105063 | 0.027 | 0.0375063 | 2.157 | 2.1345 | 5.57745 | 5.63145 | Viga -001 | yes
APTO7-VIGA-002 | 0.64035 | 0.192105 | 5.6037 | 7115 | 0 | 0.027 | 0.027 | 2.1345 | 2.1345 | 5.5497 | 5.6037 | Viga -002 | no
APTO7-VIGA-003 | 0.64035 | 0.192105 | 5.6037 | 7115 | 0 | 0.027 | 0.027 | 2.1345 | 2.1345 | 5.5497 | 5.6037 | Viga -003 | no
APTO7-VIGA-004 | 0.64035 | 0.192105 | 5.6037 | 7115 | 0 | 0.027 | 0.027 | 2.1345 | 2.1345 | 5.5497 | 5.6037 | Viga -004 | no
APTO7-VIGA-005 | 0.64035 | 0.192105 | 5.6037 | 7115 | 0 | 0.027 | 0.027 | 2.1345 | 2.1345 | 5.5497 | 5.6037 | Viga -005 | no
APTO7-VIGA-008 | 0.6471 | 0.19413 | 5.6622 | 7190 | 0.027 | 0.027 | 0.054 | 2.157 | 2.157 | 5.6082 | 5.6622 | Viga -008 | yes
APTO7-VIGA-006 | 0.64035 | 0.192105 | 5.6037 | 7115 | 0 | 0.027 | 0.027 | 2.1345 | 2.1345 | 5.5497 | 5.6037 | Viga -006 | no
APTO7-VIGA-007 | 0.64035 | 0.192105 | 5.6037 | 7115 | 0 | 0.027 | 0.027 | 2.1345 | 2.1345 | 5.5497 | 5.6037 | Viga -007 | no
APTO8-VIGA-001 | 0.642977 | 0.192893 | 5.65395 | 7190 | 0.0105063 | 0.027 | 0.0375063 | 2.1345 | 2.157 | 5.57745 | 5.63145 | Viga -001 | yes
APTO8-VIGA-002 | 0.64035 | 0.192105 | 5.6037 | 7115 | 0 | 0.027 | 0.027 | 2.1345 | 2.1345 | 5.5497 | 5.6037 | Viga -002 | no
APTO8-VIGA-003 | 0.64035 | 0.192105 | 5.6037 | 7115 | 0 | 0.027 | 0.027 | 2.1345 | 2.1345 | 5.5497 | 5.6037 | Viga -003 | no
APTO8-VIGA-004 | 0.64035 | 0.192105 | 5.6037 | 7115 | 0 | 0.027 | 0.027 | 2.1345 | 2.1345 | 5.5497 | 5.6037 | Viga -004 | no
APTO8-VIGA-005 | 0.64035 | 0.192105 | 5.6037 | 7115 | 0 | 0.027 | 0.027 | 2.1345 | 2.1345 | 5.5497 | 5.6037 | Viga -005 | no
APTO8-VIGA-008 | 0.6471 | 0.19413 | 5.6622 | 7190 | 0.027 | 0.027 | 0.054 | 2.157 | 2.157 | 5.6082 | 5.6622 | Viga -008 | yes
APTO8-VIGA-006 | 0.64035 | 0.192105 | 5.6037 | 7115 | 0 | 0.027 | 0.027 | 2.1345 | 2.1345 | 5.5497 | 5.6037 | Viga -006 | no
APTO8-VIGA-007 | 0.64035 | 0.192105 | 5.6037 | 7115 | 0 | 0.027 | 0.027 | 2.1345 | 2.1345 | 5.5497 | 5.6037 | Viga -007 | no

# IfcColumn: Concreto Armado Moldado in Loco - Estrutural 600 x 150 (12)
In: Segundo Pavimento
Classification: Pilar (Classificação ARCHICAD); 3E 12 10 02 02 Pilar (NBR 15965-5 3E); Material: Concreto Armado Moldado in Loco - Estrutural
AC_Pset_RenovationAndPhasing - Renovation Status: Existing
ArchiCADQuantities - Área: 0.09; Altura: 2650; Volume (Líquido): 0.2385; Largura: 600; Elevação à Origem do Projeto: 2650; Elevação ao 1º Nível de Referência: 2650; Elevação ao 2º Nível de Referência: 2650; Elevação ao Nível do Mar: 2650; Elevação ao Piso: 0; Afastamento da Origem: 0; Área da Superfície: 3.975; Comprimento 3D: 2650; Volume (Bruto): 0.2385; Elevação do Topo ao Primeiro Nível de Referência: 5300; Elevação do Topo Ao Piso de Origem: 2650; Elevação do Topo À Cota Zero: 5300; Elevação do Topo Ao Nível do Mar: 5300; Elevação do Topo Ao Segundo Nível de Referência: 5300; Elevação da Base Ao Primeiro Nível de Referência: 2650; Elevação da Base Ao Piso de Origem: 0; Elevação da Base À Cota Zero: 2650; Elevação da Base Ao Nível do Mar: 2650; Elevação da Base Ao Segundo Nível de Referência: 2650; Altura do Corte Transversal no Topo/Terminação (perpendicular): 150; Altura do Corte Transversal na Base/Início (perpendicular): 150; Largura do Corte Transversal no Topo/Terminação (perpendicular): 600; Largura do Corte Transversal na Base/Início (perpendicular): 600; Altura do Corte Transversal no Topo/Terminação (corte): 150; Altura do Corte Transversal na Base/Início (corte): 150; Largura do Corte Transversal no Topo/Terminação (corte): 600; Largura do Corte Transversal na Base/Início (corte): 600; Área do Corte Transversal na Base/Início: 0.09; Altura do Corte Transversal no Topo/Terminação: 0.09; Número de Segmentos: 1; Área da Superfície do Topo (Líquida): 0.09; Área da Superfície da Base (Líquida): 3.975; Afastamento do Topo: 0; Área da Superfície do Topo (Bruta): 0.09; Diâmetro / Altura do Núcleo: 150; Volume do Núcleo do Pilar (Líquido): 0.2385; Largura Núcleo: 600; Área da Superfície do Núcleo do Pilar (Bruta, sem Topo/Base): 3.975; Área da Superfície do Topo do Núcleo do Pilar (Bruta): 0.09; Área da Superfície da Base do Núcleo do Pilar (Bruta): 0.09; Volume do Núcleo do Pilar (Bruto): 0.2385; Área de Superfície do Revestimento do Pilar (Bruta, sem Topo/Base): 0; Área da Superfície do Topo do Revestimento do Pilar (Bruta): 0; Área da Superfíciena da Base do Revestimento do Pilar (Bruta): 0; Volume do Revestimento do Pilar (Bruto): 0; Altura máxima do pilar: 2650; Altura mínima do pilar: 2650; Área da Superfície da Base do Núcleo do Pilar (Líquida): 0.09; Área da Superfície do Núcleo do Pilar (Líquida, sem Topo/Base): 3.975; Área da Superfície do Topo do Núcleo do Pilar (Líquida): 0.09; Área da Superfície da Base do Revestimento do Pilar (Líquida): 0; Área da Superfície do Revestimento do Pilar (Líquida): 0; Área da Superfície do Topo do Revestimento do Pilar (Líquida): 0; Perímetro do Perfil da Coluna (base): 1500; Volume do Revestimento do Pilar (Líquido): 0
BaseQuantities - Length: 2650; Width: 600; Depth: 150; CrossSectionArea: 0.09; OuterSurfaceArea: 3.975; TotalSurfaceArea: 4.155; GrossSurfaceArea: 4.155; GrossVolume: 0.2385; NetVolume: 0.2385
ESTRUTURA (Expressão) - Custo por Volume (m3): 0
Pset_ColumnCommon - Reference: Concreto Armado Moldado in Loco - Estrutural 600 x 150; LoadBearing: yes
Name | ID Dinâmico por Classificação | IsExternal
CIRC2-PILAR-004 | Pilar -004 | no
APTO5-PILAR-000 | Pilar -000 | yes
APTO5-PILAR-001 | Pilar -001 | yes
CIRC2-PILAR-003 | Pilar -003 | no
CIRC2-PILAR-005 | Pilar -005 | no
APTO6-PILAR-000 | Pilar -000 | yes
APTO6-PILAR-001 | Pilar -001 | yes
APTO7-PILAR-000 | Pilar -000 | yes
APTO7-PILAR-001 | Pilar -001 | yes
APTO8-PILAR-000 | Pilar -000 | yes
APTO8-PILAR-001 | Pilar -001 | yes
CIRC2-PILAR-002 | Pilar -002 | no

# IfcDoor: Porta 25 (10)
In: Segundo Pavimento
Type - OperationType: SINGLE_SWING_LEFT; ParameterTakesPrecedence: no; Sizeable: no
Type - IfcDoorPanelProperties - PanelOperation: SWINGING; PanelPosition: MIDDLE
OverallHeight: 2100 mm; Classification: Porta (Classificação ARCHICAD); 3E 20 02 02 04 Porta de girar (NBR 15965-5 3E)
AC_Equantity_Porta_25 - Altura-3: 2100; Dimensão Z: 1000; Nível da Base: 1000; Nível do Topo: 0; Altura Peitoril ao Piso Atual: 0; Abertura para o Núcleo da Parede: 0; Nova Largura Direita da Trama de Parede: 150; Nova Largura Esquerda da Trama de Parede: 150; Altura Ombro: 1840; Luz Lateral com 1 Largura (gs_sidelight_width_right): 0; Luz Lateral com 1 Largura (gs_sidelight_width_right_half): 150; Luz Lateral com 1 Largura (gs_sidelight_width_right_orig): 300; Luz Lateral com 1 Altura de Soleira: 0; Luz Lateral com 2 Larguras (gs_sidelight_width_left): 0; Luz Lateral com 2 Larguras (gs_sidelight_width_left_half): 300; Luz Lateral com 2 Larguras (gs_sidelight_width_left_orig): 600; Luz Lateral com 2 Alturas de Soleira: 0; Altura Bandeira: 300; Distância Eixo Pivot: 275; Tolerância Lateral 1: 0; Tolerância Lateral 1 Inferior: 0; Tolerância Base Luz Lateral Base1: 0; Tolerância Lateral 2: 0; Tolerância Lateral 2 Inferior: 0; Tolerância Base 2 Luz Lateral: 0; Tolerância Superior: 0; Tolerância Inferior: 0; Altura de Vão: 2100; Altura Face de Vão: 2100; Altura Unidade: 2100; Altura Saída: 2050; Altura Nominal da Folha: 2060; Espessura Batente: 115; Espessura Interior Moldura: 115; Afastam. Folha: 0; Largura Batente: 50; Batente Sobredimensionado: 10; Espessura do Batente Externo: 10; Largura Moldura Lado 1: 40; Largura Moldura Meio Lado 1: 40; Largura Moldura Inferior Lado 1: 40; Largura Batente Lado 2: 40; Largura Moldura Meio Lado 2: 40; Largura Moldura Inferior Lado 2: 40; Largura Moldura Bandeira (gs_frame_width_transom): 40; Largura Batente Cimo: 40; Espessura Porta de Paragem: 32; Largura Porta de Paragem: 16; Largura Rebaixo: 10; Profundidade do Rebaixo da folha em 3D: 30; Largura do Rebaixo da Luz Lateral e Bandeira: 10; Profund. de Rebaixo da Luz Lateral e Bandeira: 18; Espessura Folha: 30; Largura Batente Folha Lateral: 100; Largura Moldura Folha Direita: 100; Largura Moldura Folha Esquerda: 100; Largura Batente Folha Inferior: 200; Largura Batente Folha Superior: 100; Largura Folha Interna: 25; Recorte inferior da folha: 0; Largura Grelha (gs_grid_w): 12; Espessura Grelha (gs_grid_thk): 25; Espessura Vidro: 12; Altura Maçaneta: 1000; Posição Maçaneta: 50; Altura Proteção Borda: 100; Altura Divisão Horizontal Luz Lateral Lado 1: 900; Altura Divisão Horizontal Luz Lateral Lado 2: 900; Altura Divisão Horizontal Bandeira Meio: 900; Altura Divisão Horizontal Bandeira Lado 1: 900; Altura Divisão Horizontal Bandeira Lado 2: 900; Espessura Batente Luz Lateral e Bandeira: 44; Largura Moldura Bandeira (gs_sash_width): 67; Largura batente Painel Lateral: 67; Largura Grelha (gw): 20; Espessura Grelha (gth): 25; Largura Divisão Luz Lateral: 40; Espessura Divisão Luz Lateral: 40; Largura Arquitrave Principal: 20; Largura Lado 1 (gs_tw_right_out): 70; Largura Lado 2 (gs_tw_left_out): 50; Largura Topo (gs_tw_top_out): 50; Espessura de Parede (gs_trim_thk_out): 19; Espessura na Abertura da Parede (gs_trim_width_out): 25; Paralelas (gs_trim_offs_out): 15; Bordo (gs_trim_jambext_nosing_out): 50; Saliência Superior (gs_trimov_top_left_out): 0; Saliência Superior (gs_trimov_top_right_out): 0; Largura Lado 1 (gs_tw_right_in): 70; Largura Lado 2 (gs_tw_left_in): 50; Largura Topo (gs_tw_top_in): 50; Espessura de Parede (gs_trim_thk_in): 19; Espessura na Abertura da Parede (gs_trim_width_in): 25; Paralelas (gs_trim_offs_in): 15; Bordo (gs_trim_jambext_nosing_in): 50; Saliência Superior (gs_trimov_top_left_in): 0; Saliência Superior (gs_trimov_top_right_in): 0; Espessura Soleira: 12; Largura Soleira: 10; Espessura Externa Soleira: 5.80738; Testeira Externa Soleira: 10; Avanço Soleira Interna: 10; Saliência Lateral Externo: 0; Saliência Lateral Interno: 0; Espessura Peitoril: 100; Espessura Lateral da Frente Peitoril: 15; Elevação Peitoril: 5; Recobrimento Goteira Peitoril: 20; Largura Goteira Peitoril: 30; Testeira Peitoril: 45; Avanço Lateral Peitoril 1: 0; Avanço Lateral Peitoril 2: 0; Inclinação do Parapeito: 35; Largura Topo Parapeito: 10; Altura Topo Peitoril: 10; Inclin. Peitoril da Parede: 0; Profund. Vão Posterior (gs_sill_holeDepthBehind): 0; Largura Peitoril: 80; Espessura do Tijolo (gs_brick_sill_br_thk): 65; Espessura de Argamassa (gs_brick_sill_mort_thk): 15; Largura Peitoril Int.: 100; Espessura Peitoril Int.: 25; Peitoril Int. Arredondado: 30; Avanço Lateral Peitoril Interno 1: 0; Avanço Lateral Peitoril Interno 2: 0; Inclinação do Parapeito Int.: 0; Altura Perfil: 65; Espessura Perfil: 110; Altura Painel: 2088; Afast. Interior: 20; Profund. Fechamento: 0; Largura Batente Extra: 40; Espess. Batente Extra: 30; Largura Barra:: 30; Comprim. Vara Suspensa: 20; Raio Vara Suspensa: 5; Distância Painel: 6; Saliência Exterior: 0; Largura Painel Interior: 120; Comprim. Abertura 3D: 1500; Comprim. Fechado 3D: 0; Comprimento 1 Abertura 3D: 560; Comprimento 2 Abertura 3D: 140; Altura Abertura 3D: 1500; Altura Fechado 3D: 0; Espessura Painel: 50; Largura Estrutura Painel: 50; Largura Moldura Inferior: 50; Largura Painel: 388; Espess. de Enchimento de Painel: 10; Espessura da Veneziana: 10; Largura Grelha Ventilação: 40; Largura Divisor Moldura Horiz.: 50; Largura de Divisor Moldura Vert.: 50; Raio do Vão: 10; Largura Bordo Vertical: 100; Largura Estrutura Z: 50; Espessura Estrutura Z: 25; Espess. Placas Verticais: 25; Espess. Placas Horizontais: 25; Largura Aprox. Placas Verticais: 80; Largura Aprox. Placas Horizontais: 115; Altura Caixa (gs_shutRoll_boxHeight): 200; Profund. Caixa (gs_shutRoll_boxWidth): 150; Afast. Caixa Esq.: 0; Afast. Caixa Dir.: 0; Profund. Anteparos: 72.5; Distância da Parede (gs_shutRoll_distFromWall): 0; Distância da Padieira (gs_shutRoll_distFromHead): 0; Largura da Ripa: 50; Altura Caixa (gs_shutLam_boxHeight): 200; Profund. Caixa (gs_shutLam_boxWidth): 150; Largura Capa: 0; Distância da Parede (gs_shutLam_distFromWall): 0; Distância da Padieira (gs_shutLam_distFromHead): 0; Largura Segmento (gs_shutLam_segmentWidth): 60; Altura Caixa (gs_shutLam2_boxHeight): 60; Largura Caixa: 60; Distância da Janela: 60; Distância da Padieira (gs_shutLam2_distFromHead): 60; Altura do Eixo da Caixa da Padieira: 0; Largura Segmento (gs_shutLam2_segmentWidth): 60; Distância entre Arco e Porta: 0; Arco Alvenaria Avanço Lado 1: 0; Arco Alvenaria Avanço Lado 2: 0; Espelho do Arco de Alvenaria: 30; Projeção do Arco de Alvenaria: 0; Altura do Arco de Alvenaria: 250; Profundidade do Arco de Alvenaria: 120; Profund. Vão Posterior (gs_masonry_arch_rearHoleDepth): 0; Espessura do Tijolo (gs_masonry_arch_brick_thk): 65; Espessura de Argamassa (gs_masonry_arch_mort_thk): 10; Largura Fecho: 100; Sobredimensão Fecho: 0; Projeção Fecho: 10; Profund. Face de Vão (gs_wido_sill): 0; Profund. Face de Vão (AC_wido_sill): 0; Profund. Ombreira: 60; Profund. Ombreira Lado 2: 60; Profund. Ombreira Inferior Lado 1: 60; Profund. Ombreira Inferior Lado 2: 60; Profund. Ombreira Interior Lado 2 (gs_reveal_splayed_innerLeft): 60; Profund. Ombreira Interior (gs_reveal_splayed_innerRight): 60; Profund. Ombreira Interior (gs_reveal_double_innerRight): 60; Profund. Ombreira Interior Lado 2 (gs_reveal_double_innerLeft): 60; Profund. Ombreira Interior Inferior Lado 1: 60; Profund. Ombreira Interior Inferior Lado 2: 60; Profund. do Topo: 60; Profundidade Peitoril: 60; Profund. Peitoril Lado 1: 60; Profund. Peitoril Lado 2: 60; Profundidade Padieira Interior (gs_reveal_splayed_innerTop): 60; Profundidade Peitoril Interior (gs_reveal_splayed_innerBottom): 0; Profundidade Padieira Interior (gs_reveal_double_innerTop): 60; Profundidade Peitoril Interior (gs_reveal_double_innerBottom): 0; Profund. Peitoril Interior Lado 1: 0; Profund. Peitoril Interior Lado 2: 0; Profund. Batente Exterior: 80; Limite Espess. Reboco: 40; Distância de Camada do Encerram.: 0; Largura do Fecho: 38; Espessura do Fecho: 100; Espessura da Camada: 25; Espessura do Perfil: 150; Espessura Personal.: 15; Saliência Camada para Espess. Batente: 0; Sobred. Abertura Esquerda: 0; Sobred. Direita Abertura: 0; Sobred. Topo Abertura: 0; Sobred. Base Abertura: 0; Largura Abertura 3D: 0; Largura Abertura em 3D no Lado 2: 0; Largura Abertura 2D: 0; Largura Abertura em 2D no Lado 2: 0; Distância Abertura 1 Caixilho Principal Lado 1: 0; Distância Abertura 2 Caixilho Principal Lado 1: 0; Distância Abertura 1 Caixilho Principal Lado 2: 0; Distância Abertura 2 Caixilho Principal Lado 2: 0; Distância Abertura 1 Bandeira Meio: 0; Distância Abertura 2 Bandeira Meio: 0; Distância Abertura 1 Bandeira Lado 1: 0; Distância Abertura 2 Bandeira Lado 1: 0; Distância Abertura 1 Bandeira Lado 2: 0; Distância Abertura 2 Bandeira Lado 2: 0; Largura 2 de Lado de Abertura: 200; Largura 1 de Lado de Abertura: 100; Profund. Lado de Abertura: 1000; Largura 2 de Lado Oposto: 100; Largura 1 de Lado Oposto: 100; Profund. Lado Oposto: 1000; Sobred. Abertura Esq. AC: 0; Sobred. Abertura Dir. AC: 0; Sobred. Padieira AC: 0; Sobred. Abertura Base AC: 0; ID Afastamento X: 0; ID Afastamento Y: 0; Afastamento X Texto Personalizado: 0; Afastasmento Y Texto Personalizado: 0; Afastamento X Largura da Folha: 0; Afastamento Y Largura da Folha: 0
AC_Pset_RenovationAndPhasing - Renovation Status: Existing
ArchiCADQuantities - Altura: 2100; Elevação à Origem do Projeto: 2650; Elevação ao 1º Nível de Referência: 2650; Elevação ao 2º Nível de Referência: 2650; Elevação ao Nível do Mar: 2650; Elevação ao Piso: 0; Afastamento da Origem: 0; Elevação do Topo ao Primeiro Nível de Referência: 4750; Elevação do Topo Ao Piso de Origem: 2100; Elevação do Topo À Cota Zero: 4750; Elevação do Topo Ao Nível do Mar: 4750; Elevação do Topo Ao Segundo Nível de Referência: 4750; Elevação da Base Ao Primeiro Nível de Referência: 2650; Elevação da Base Ao Piso de Origem: 0; Elevação da Base À Cota Zero: 2650; Elevação da Base Ao Nível do Mar: 2650; Elevação da Base Ao Segundo Nível de Referência: 2650; P/J Altura do Vão no Lado Oposto do Requadro: 2100; P/J Altura do Vão no Lado do Requadro: 2100; P/J Altura do Vão Nominal no Lado Oposto do Requadro: 2100; P/J Altura do Vão Nominal no Lado do Requadro: 2100; Altura da Soleira/Peitoril ou Padieira: 0; P/J Altura Nominal do Parapeito: 0; P/J Altura do Parapeito no Lado do Requadro: 0; P/J Altura do Parapeito no Lado Oposto do Requadro: 0; P/J Altura Nominal da Padieira: 2100; P/J Altura da Padiera no Lado Oposto do Requadro: 2100; P/J Altura da Padiera no Lado do Requadro: 2100
BaseQuantities - Height: 2100
CLASSIFICAÇÕES GERAIS - Transmissão Sonora: 0
FABRICAÇÃO - Data de Fabricação: DD/MM/YYYY; Site do Produto: www.graphisoft.com
GARANTIA - Ínicio da Garantia: DD/MM/YYYY; Fim da Garantia: DD/MM/YYYY
INFORMAÇÕES DO PRODUTO - Data de Aquisição: DD/MM/YYYY
Pset_DoorCommon - ThermalTransmittance: 0
Name | OverallWidth (mm) = Largura-2 = Largura de Vão = Largura Face de Vão = Largura Unidade = Largura = P/J Largura do Vão no Lado Oposto do Requadro = P/J Largura do Vão no Lado do Requadro = P/J Largura do Vão Nominal no Lado Oposto do Requadro = P/J Largura do Vão Nominal no Lado do Requadro = Width | Largura Saída | Largura Nominal da Folha | Largura Nominal da Folha no Lado 1 | Espessura Moldura Real = Espessura da Parede = Espessura do Batente = Depth | Volume (Líquido) = NetVolume = Volume | Área da Superfície = Área da Superfície da Base (Líquida) = Abertura Área da Superfície L/D | Abertura Volume de Vão L/D = P/J Volume Nominal da Abertura | P/J Área de Superfície Nominal do Vão = Área da Superfície da Abertura no Lado do Requadro da J/P = Área da Superfície da Abertura no Lado Oposto ao Requadro da J/P = P/J Área da Superfície do Vão Nominal no Lado do Requadro = P/J Área da Superfície do Vão Nominal no Lado Oposto do Requadro = Area | Perimeter | ID Dinâmico por Classificação | Localização do Produto no Projeto | ID de Aberturas com Master ID | IsExternal
APTO5-PORTA-001 | 900 | 800 | 820 | 360 | 40 | 0.0592503 | 4.51191 | 0.0756 | 1.89 | 6000 | Porta -001 | Projeto: CECAP GuarulhosLocal: Piso: Segundo Pavimento Cômodo: | APTO5-001 | no
APTO5-PORTA-003 | 710 | 610 | 630 | 315 | 90 | 0.0592103 | 4.17951 | 0.13419 | 1.491 | 5620 | Porta -003 | Projeto: CECAP GuarulhosLocal: Piso: Segundo Pavimento Cômodo: WC | APTO5-13003 | no
APTO5-PORTA-004 | 900 | 800 | 820 | 360 | 140 | 0.0842503 | 5.54191 | 0.2646 | 1.89 | 6000 | Porta -004 | Projeto: CECAP GuarulhosLocal: Piso: Segundo Pavimento Cômodo: SALA | APTO5-09004 | yes
APTO6-PORTA-002 | 900 | 800 | 820 | 360 | 40 | 0.0592503 | 4.51191 | 0.0756 | 1.89 | 6000 | Porta -002 | Projeto: CECAP GuarulhosLocal: Piso: Segundo Pavimento Cômodo: | APTO6-002 | no
APTO6-PORTA-000 | 900 | 800 | 820 | 360 | 40 | 0.0592503 | 4.51191 | 0.0756 | 1.89 | 6000 | Porta -000 | Projeto: CECAP GuarulhosLocal: Piso: Segundo Pavimento Cômodo: | APTO6-000 | no
APTO7-PORTA-002 | 900 | 800 | 820 | 360 | 40 | 0.0592503 | 4.51191 | 0.0756 | 1.89 | 6000 | Porta -002 | Projeto: CECAP GuarulhosLocal: Piso: Segundo Pavimento Cômodo: | APTO7-002 | no
APTO7-PORTA-000 | 900 | 800 | 820 | 360 | 40 | 0.0592503 | 4.51191 | 0.0756 | 1.89 | 6000 | Porta -000 | Projeto: CECAP GuarulhosLocal: Piso: Segundo Pavimento Cômodo: | APTO7-000 | no
APTO8-PORTA-003 | 710 | 610 | 630 | 315 | 90 | 0.0592103 | 4.17951 | 0.13419 | 1.491 | 5620 | Porta -003 | Projeto: CECAP GuarulhosLocal: Piso: Segundo Pavimento Cômodo: WC | APTO8-13003 | no
APTO8-PORTA-004 | 900 | 800 | 820 | 360 | 140 | 0.0842503 | 5.54191 | 0.2646 | 1.89 | 6000 | Porta -004 | Projeto: CECAP GuarulhosLocal: Piso: Segundo Pavimento Cômodo: CORREDOR | APTO8-33004 | yes
APTO8-PORTA-001 | 900 | 800 | 820 | 360 | 40 | 0.0592503 | 4.51191 | 0.0756 | 1.89 | 6000 | Porta -001 | Projeto: CECAP GuarulhosLocal: Piso: Segundo Pavimento Cômodo: | APTO8-001 | no

# IfcDoor: Porta 25 (10)
In: Segundo Pavimento
Type - OperationType: SINGLE_SWING_RIGHT; ParameterTakesPrecedence: no; Sizeable: no
Type - IfcDoorPanelProperties - PanelOperation: SWINGING; PanelPosition: MIDDLE
OverallHeight: 2100 mm; Classification: Porta (Classificação ARCHICAD); 3E 20 02 02 04 Porta de girar (NBR 15965-5 3E)
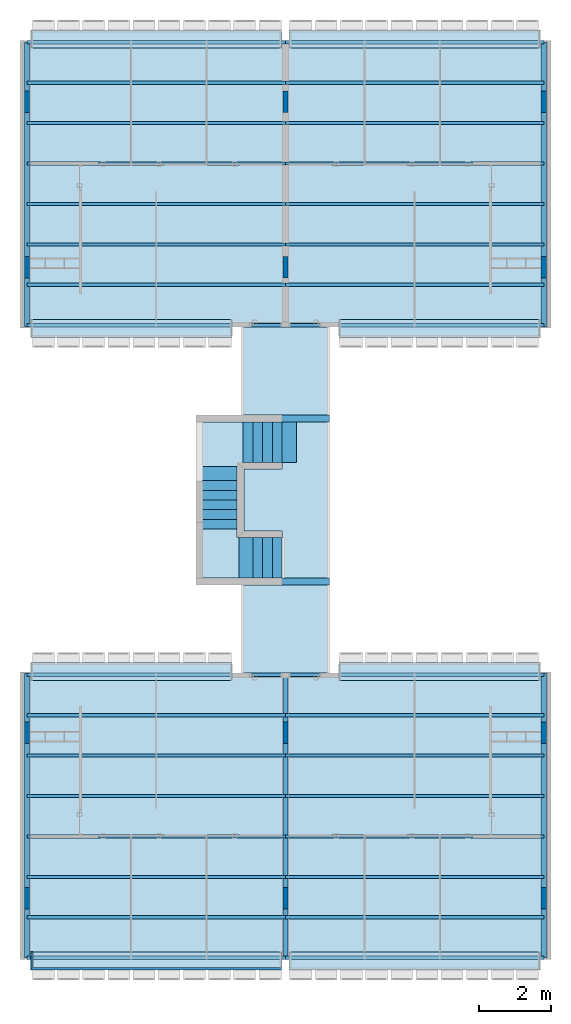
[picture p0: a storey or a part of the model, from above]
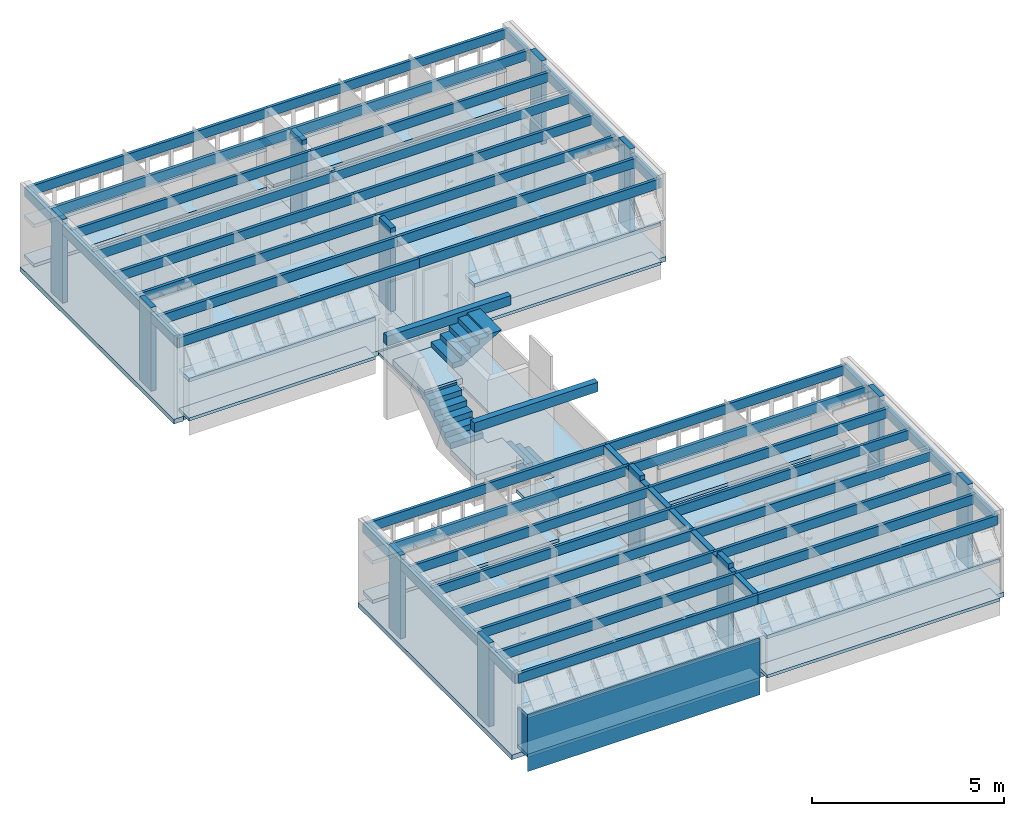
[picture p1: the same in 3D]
Properties of the parts of a building model (IFC2X3), part 2 of 3

# IfcDoor: Porta 25 (10)
AC_Equantity_Porta_25 - Altura-3: 2100; Dimensão Z: 1000; Nível da Base: 1000; Nível do Topo: 0; Altura Peitoril ao Piso Atual: 0; Abertura para o Núcleo da Parede: 0; Nova Largura Direita da Trama de Parede: 150; Nova Largura Esquerda da Trama de Parede: 150; Altura Ombro: 1840; Luz Lateral com 1 Largura (gs_sidelight_width_right): 0; Luz Lateral com 1 Largura (gs_sidelight_width_right_half): 150; Luz Lateral com 1 Largura (gs_sidelight_width_right_orig): 300; Luz Lateral com 1 Altura de Soleira: 0; Luz Lateral com 2 Larguras (gs_sidelight_width_left): 0; Luz Lateral com 2 Larguras (gs_sidelight_width_left_half): 300; Luz Lateral com 2 Larguras (gs_sidelight_width_left_orig): 600; Luz Lateral com 2 Alturas de Soleira: 0; Altura Bandeira: 300; Distância Eixo Pivot: 275; Tolerância Lateral 1: 0; Tolerância Lateral 1 Inferior: 0; Tolerância Base Luz Lateral Base1: 0; Tolerância Lateral 2: 0; Tolerância Lateral 2 Inferior: 0; Tolerância Base 2 Luz Lateral: 0; Tolerância Superior: 0; Tolerância Inferior: 0; Altura de Vão: 2100; Altura Face de Vão: 2100; Altura Unidade: 2100; Altura Saída: 2050; Altura Nominal da Folha: 2060; Espessura Batente: 115; Espessura Interior Moldura: 115; Afastam. Folha: 0; Largura Batente: 50; Batente Sobredimensionado: 10; Espessura do Batente Externo: 10; Largura Moldura Lado 1: 40; Largura Moldura Meio Lado 1: 40; Largura Moldura Inferior Lado 1: 40; Largura Batente Lado 2: 40; Largura Moldura Meio Lado 2: 40; Largura Moldura Inferior Lado 2: 40; Largura Moldura Bandeira (gs_frame_width_transom): 40; Largura Batente Cimo: 40; Espessura Porta de Paragem: 32; Largura Porta de Paragem: 16; Largura Rebaixo: 10; Profundidade do Rebaixo da folha em 3D: 30; Largura do Rebaixo da Luz Lateral e Bandeira: 10; Profund. de Rebaixo da Luz Lateral e Bandeira: 18; Espessura Folha: 30; Largura Batente Folha Lateral: 100; Largura Moldura Folha Direita: 100; Largura Moldura Folha Esquerda: 100; Largura Batente Folha Inferior: 200; Largura Batente Folha Superior: 100; Largura Folha Interna: 25; Recorte inferior da folha: 0; Largura Grelha (gs_grid_w): 12; Espessura Grelha (gs_grid_thk): 25; Espessura Vidro: 12; Altura Maçaneta: 1000; Posição Maçaneta: 50; Altura Proteção Borda: 100; Altura Divisão Horizontal Luz Lateral Lado 1: 900; Altura Divisão Horizontal Luz Lateral Lado 2: 900; Altura Divisão Horizontal Bandeira Meio: 900; Altura Divisão Horizontal Bandeira Lado 1: 900; Altura Divisão Horizontal Bandeira Lado 2: 900; Espessura Batente Luz Lateral e Bandeira: 44; Largura Moldura Bandeira (gs_sash_width): 67; Largura batente Painel Lateral: 67; Largura Grelha (gw): 20; Espessura Grelha (gth): 25; Largura Divisão Luz Lateral: 40; Espessura Divisão Luz Lateral: 40; Largura Arquitrave Principal: 20; Largura Lado 1 (gs_tw_right_out): 70; Largura Lado 2 (gs_tw_left_out): 50; Largura Topo (gs_tw_top_out): 50; Espessura de Parede (gs_trim_thk_out): 19; Espessura na Abertura da Parede (gs_trim_width_out): 25; Paralelas (gs_trim_offs_out): 15; Bordo (gs_trim_jambext_nosing_out): 50; Saliência Superior (gs_trimov_top_left_out): 0; Saliência Superior (gs_trimov_top_right_out): 0; Largura Lado 1 (gs_tw_right_in): 70; Largura Lado 2 (gs_tw_left_in): 50; Largura Topo (gs_tw_top_in): 50; Espessura de Parede (gs_trim_thk_in): 19; Espessura na Abertura da Parede (gs_trim_width_in): 25; Paralelas (gs_trim_offs_in): 15; Bordo (gs_trim_jambext_nosing_in): 50; Saliência Superior (gs_trimov_top_left_in): 0; Saliência Superior (gs_trimov_top_right_in): 0; Espessura Soleira: 12; Largura Soleira: 10; Espessura Externa Soleira: 5.80738; Testeira Externa Soleira: 10; Avanço Soleira Interna: 10; Saliência Lateral Externo: 0; Saliência Lateral Interno: 0; Espessura Peitoril: 100; Espessura Lateral da Frente Peitoril: 15; Elevação Peitoril: 5; Recobrimento Goteira Peitoril: 20; Largura Goteira Peitoril: 30; Testeira Peitoril: 45; Avanço Lateral Peitoril 1: 0; Avanço Lateral Peitoril 2: 0; Inclinação do Parapeito: 35; Largura Topo Parapeito: 10; Altura Topo Peitoril: 10; Inclin. Peitoril da Parede: 0; Profund. Vão Posterior (gs_sill_holeDepthBehind): 0; Largura Peitoril: 80; Espessura do Tijolo (gs_brick_sill_br_thk): 65; Espessura de Argamassa (gs_brick_sill_mort_thk): 15; Largura Peitoril Int.: 100; Espessura Peitoril Int.: 25; Peitoril Int. Arredondado: 30; Avanço Lateral Peitoril Interno 1: 0; Avanço Lateral Peitoril Interno 2: 0; Inclinação do Parapeito Int.: 0; Altura Perfil: 65; Espessura Perfil: 110; Altura Painel: 2088; Afast. Interior: 20; Profund. Fechamento: 0; Largura Batente Extra: 40; Espess. Batente Extra: 30; Largura Barra:: 30; Comprim. Vara Suspensa: 20; Raio Vara Suspensa: 5; Distância Painel: 6; Saliência Exterior: 0; Largura Painel Interior: 120; Comprim. Abertura 3D: 1500; Comprim. Fechado 3D: 0; Comprimento 1 Abertura 3D: 560; Comprimento 2 Abertura 3D: 140; Altura Abertura 3D: 1500; Altura Fechado 3D: 0; Espessura Painel: 50; Largura Estrutura Painel: 50; Largura Moldura Inferior: 50; Largura Painel: 388; Espess. de Enchimento de Painel: 10; Espessura da Veneziana: 10; Largura Grelha Ventilação: 40; Largura Divisor Moldura Horiz.: 50; Largura de Divisor Moldura Vert.: 50; Raio do Vão: 10; Largura Bordo Vertical: 100; Largura Estrutura Z: 50; Espessura Estrutura Z: 25; Espess. Placas Verticais: 25; Espess. Placas Horizontais: 25; Largura Aprox. Placas Verticais: 80; Largura Aprox. Placas Horizontais: 115; Altura Caixa (gs_shutRoll_boxHeight): 200; Profund. Caixa (gs_shutRoll_boxWidth): 150; Afast. Caixa Esq.: 0; Afast. Caixa Dir.: 0; Profund. Anteparos: 72.5; Distância da Parede (gs_shutRoll_distFromWall): 0; Distância da Padieira (gs_shutRoll_distFromHead): 0; Largura da Ripa: 50; Altura Caixa (gs_shutLam_boxHeight): 200; Profund. Caixa (gs_shutLam_boxWidth): 150; Largura Capa: 0; Distância da Parede (gs_shutLam_distFromWall): 0; Distância da Padieira (gs_shutLam_distFromHead): 0; Largura Segmento (gs_shutLam_segmentWidth): 60; Altura Caixa (gs_shutLam2_boxHeight): 60; Largura Caixa: 60; Distância da Janela: 60; Distância da Padieira (gs_shutLam2_distFromHead): 60; Altura do Eixo da Caixa da Padieira: 0; Largura Segmento (gs_shutLam2_segmentWidth): 60; Distância entre Arco e Porta: 0; Arco Alvenaria Avanço Lado 1: 0; Arco Alvenaria Avanço Lado 2: 0; Espelho do Arco de Alvenaria: 30; Projeção do Arco de Alvenaria: 0; Altura do Arco de Alvenaria: 250; Profundidade do Arco de Alvenaria: 120; Profund. Vão Posterior (gs_masonry_arch_rearHoleDepth): 0; Espessura do Tijolo (gs_masonry_arch_brick_thk): 65; Espessura de Argamassa (gs_masonry_arch_mort_thk): 10; Largura Fecho: 100; Sobredimensão Fecho: 0; Projeção Fecho: 10; Profund. Face de Vão (gs_wido_sill): 0; Profund. Face de Vão (AC_wido_sill): 0; Profund. Ombreira: 60; Profund. Ombreira Lado 2: 60; Profund. Ombreira Inferior Lado 1: 60; Profund. Ombreira Inferior Lado 2: 60; Profund. Ombreira Interior Lado 2 (gs_reveal_splayed_innerLeft): 60; Profund. Ombreira Interior (gs_reveal_splayed_innerRight): 60; Profund. Ombreira Interior (gs_reveal_double_innerRight): 60; Profund. Ombreira Interior Lado 2 (gs_reveal_double_innerLeft): 60; Profund. Ombreira Interior Inferior Lado 1: 60; Profund. Ombreira Interior Inferior Lado 2: 60; Profund. do Topo: 60; Profundidade Peitoril: 60; Profund. Peitoril Lado 1: 60; Profund. Peitoril Lado 2: 60; Profundidade Padieira Interior (gs_reveal_splayed_innerTop): 60; Profundidade Peitoril Interior (gs_reveal_splayed_innerBottom): 0; Profundidade Padieira Interior (gs_reveal_double_innerTop): 60; Profundidade Peitoril Interior (gs_reveal_double_innerBottom): 0; Profund. Peitoril Interior Lado 1: 0; Profund. Peitoril Interior Lado 2: 0; Profund. Batente Exterior: 80; Limite Espess. Reboco: 40; Distância de Camada do Encerram.: 0; Largura do Fecho: 38; Espessura do Fecho: 100; Espessura da Camada: 25; Espessura do Perfil: 150; Espessura Personal.: 15; Saliência Camada para Espess. Batente: 0; Sobred. Abertura Esquerda: 0; Sobred. Direita Abertura: 0; Sobred. Topo Abertura: 0; Sobred. Base Abertura: 0; Largura Abertura 3D: 0; Largura Abertura em 3D no Lado 2: 0; Largura Abertura 2D: 0; Largura Abertura em 2D no Lado 2: 0; Distância Abertura 1 Caixilho Principal Lado 1: 0; Distância Abertura 2 Caixilho Principal Lado 1: 0; Distância Abertura 1 Caixilho Principal Lado 2: 0; Distância Abertura 2 Caixilho Principal Lado 2: 0; Distância Abertura 1 Bandeira Meio: 0; Distância Abertura 2 Bandeira Meio: 0; Distância Abertura 1 Bandeira Lado 1: 0; Distância Abertura 2 Bandeira Lado 1: 0; Distância Abertura 1 Bandeira Lado 2: 0; Distância Abertura 2 Bandeira Lado 2: 0; Largura 2 de Lado de Abertura: 200; Largura 1 de Lado de Abertura: 100; Profund. Lado de Abertura: 1000; Largura 2 de Lado Oposto: 100; Largura 1 de Lado Oposto: 100; Profund. Lado Oposto: 1000; Sobred. Abertura Esq. AC: 0; Sobred. Abertura Dir. AC: 0; Sobred. Padieira AC: 0; Sobred. Abertura Base AC: 0; ID Afastamento X: 0; ID Afastamento Y: 0; Afastamento X Texto Personalizado: 0; Afastasmento Y Texto Personalizado: 0; Afastamento X Largura da Folha: 0; Afastamento Y Largura da Folha: 0
AC_Pset_RenovationAndPhasing - Renovation Status: Existing
ArchiCADQuantities - Altura: 2100; Elevação à Origem do Projeto: 2650; Elevação ao 1º Nível de Referência: 2650; Elevação ao 2º Nível de Referência: 2650; Elevação ao Nível do Mar: 2650; Elevação ao Piso: 0; Afastamento da Origem: 0; Elevação do Topo ao Primeiro Nível de Referência: 4750; Elevação do Topo Ao Piso de Origem: 2100; Elevação do Topo À Cota Zero: 4750; Elevação do Topo Ao Nível do Mar: 4750; Elevação do Topo Ao Segundo Nível de Referência: 4750; Elevação da Base Ao Primeiro Nível de Referência: 2650; Elevação da Base Ao Piso de Origem: 0; Elevação da Base À Cota Zero: 2650; Elevação da Base Ao Nível do Mar: 2650; Elevação da Base Ao Segundo Nível de Referência: 2650; P/J Altura do Vão no Lado Oposto do Requadro: 2100; P/J Altura do Vão no Lado do Requadro: 2100; P/J Altura do Vão Nominal no Lado Oposto do Requadro: 2100; P/J Altura do Vão Nominal no Lado do Requadro: 2100; Altura da Soleira/Peitoril ou Padieira: 0; P/J Altura Nominal do Parapeito: 0; P/J Altura do Parapeito no Lado do Requadro: 0; P/J Altura do Parapeito no Lado Oposto do Requadro: 0; P/J Altura Nominal da Padieira: 2100; P/J Altura da Padiera no Lado Oposto do Requadro: 2100; P/J Altura da Padiera no Lado do Requadro: 2100
BaseQuantities - Height: 2100
CLASSIFICAÇÕES GERAIS - Transmissão Sonora: 0
FABRICAÇÃO - Data de Fabricação: DD/MM/YYYY; Site do Produto: www.graphisoft.com
GARANTIA - Ínicio da Garantia: DD/MM/YYYY; Fim da Garantia: DD/MM/YYYY
INFORMAÇÕES DO PRODUTO - Data de Aquisição: DD/MM/YYYY
Pset_DoorCommon - ThermalTransmittance: 0
Name | OverallWidth (mm) = Largura-2 = Largura de Vão = Largura Face de Vão = Largura Unidade = Largura = P/J Largura do Vão no Lado Oposto do Requadro = P/J Largura do Vão no Lado do Requadro = P/J Largura do Vão Nominal no Lado Oposto do Requadro = P/J Largura do Vão Nominal no Lado do Requadro = Width | Largura Saída | Largura Nominal da Folha | Largura Nominal da Folha no Lado 1 | Espessura Moldura Real = Espessura da Parede = Espessura do Batente = Depth | Volume (Líquido) = NetVolume = Volume | Área da Superfície = Área da Superfície da Base (Líquida) = Abertura Área da Superfície L/D | Abertura Volume de Vão L/D = P/J Volume Nominal da Abertura | P/J Área de Superfície Nominal do Vão = Área da Superfície da Abertura no Lado do Requadro da J/P = Área da Superfície da Abertura no Lado Oposto ao Requadro da J/P = P/J Área da Superfície do Vão Nominal no Lado do Requadro = P/J Área da Superfície do Vão Nominal no Lado Oposto do Requadro = Area | Perimeter | ID Dinâmico por Classificação | Localização do Produto no Projeto | ID de Aberturas com Master ID | IsExternal
APTO5-PORTA-002 | 900 | 800 | 820 | 360 | 40 | 0.0592503 | 4.51191 | 0.0756 | 1.89 | 6000 | Porta -002 | Projeto: CECAP GuarulhosLocal: Piso: Segundo Pavimento Cômodo: | APTO5-002 | no
APTO5-PORTA-000 | 900 | 800 | 820 | 360 | 40 | 0.0592503 | 4.51191 | 0.0756 | 1.89 | 6000 | Porta -000 | Projeto: CECAP GuarulhosLocal: Piso: Segundo Pavimento Cômodo: | APTO5-000 | no
APTO6-PORTA-003 | 710 | 610 | 630 | 315 | 90 | 0.0592103 | 4.17951 | 0.13419 | 1.491 | 5620 | Porta -003 | Projeto: CECAP GuarulhosLocal: Piso: Segundo Pavimento Cômodo: WC | APTO6-13003 | no
APTO6-PORTA-004 | 900 | 800 | 820 | 360 | 140 | 0.0842503 | 5.54191 | 0.2646 | 1.89 | 6000 | Porta -004 | Projeto: CECAP GuarulhosLocal: Piso: Segundo Pavimento Cômodo: SALA | APTO6-09004 | yes
APTO6-PORTA-001 | 900 | 800 | 820 | 360 | 40 | 0.0592503 | 4.51191 | 0.0756 | 1.89 | 6000 | Porta -001 | Projeto: CECAP GuarulhosLocal: Piso: Segundo Pavimento Cômodo: | APTO6-001 | no
APTO7-PORTA-003 | 710 | 610 | 630 | 315 | 90 | 0.0592103 | 4.17951 | 0.13419 | 1.491 | 5620 | Porta -003 | Projeto: CECAP GuarulhosLocal: Piso: Segundo Pavimento Cômodo: WC | APTO7-13003 | no
APTO7-PORTA-004 | 900 | 800 | 820 | 360 | 140 | 0.0842503 | 5.54191 | 0.2646 | 1.89 | 6000 | Porta -004 | Projeto: CECAP GuarulhosLocal: Piso: Segundo Pavimento Cômodo: SALA | APTO7-09004 | yes
APTO7-PORTA-001 | 900 | 800 | 820 | 360 | 40 | 0.0592503 | 4.51191 | 0.0756 | 1.89 | 6000 | Porta -001 | Projeto: CECAP GuarulhosLocal: Piso: Segundo Pavimento Cômodo: | APTO7-001 | no
APTO8-PORTA-002 | 900 | 800 | 820 | 360 | 40 | 0.0592503 | 4.51191 | 0.0756 | 1.89 | 6000 | Porta -002 | Projeto: CECAP GuarulhosLocal: Piso: Segundo Pavimento Cômodo: | APTO8-002 | no
APTO8-PORTA-000 | 900 | 800 | 820 | 360 | 40 | 0.0592503 | 4.51191 | 0.0756 | 1.89 | 6000 | Porta -000 | Projeto: CECAP GuarulhosLocal: Piso: Segundo Pavimento Cômodo: | APTO8-000 | no

# IfcMember (3)
In: Segundo Pavimento
Classification: Estrutura de Escada (Classificação ARCHICAD); Material: Concreto - Estrutural
AC_Pset_RenovationAndPhasing - Renovation Status: Existing
ArchiCADQuantities - Espessura: 150; Espessura Secundária: 150
EXPRESSÕES DE TEXTO (Expressão) - Localização do Produto no Projeto: Projeto: CECAP GuarulhosLocal: Piso: Segundo Pavimento Cômodo: ESCADA
Name | Volume (Líquido) = GrossVolume = NetVolume | Largura | Elevação à Origem do Projeto = Elevação ao 1º Nível de Referência = Elevação ao 2º Nível de Referência = Elevação ao Nível do Mar | Elevação ao Piso = Afastamento da Origem | Área da Superfície = Área da Superfície da Base (Líquida) = Área da Superfície Total | Comprimento 3D | Elevação do Topo ao Primeiro Nível de Referência = Elevação do Topo À Cota Zero = Elevação do Topo Ao Nível do Mar = Elevação do Topo Ao Segundo Nível de Referência | Elevação do Topo Ao Piso de Origem | Elevação da Base Ao Primeiro Nível de Referência = Elevação da Base À Cota Zero = Elevação da Base Ao Nível do Mar = Elevação da Base Ao Segundo Nível de Referência | Elevação da Base Ao Piso de Origem | Afastamento do Topo | Altura 3D Estrutura da Escada | ID Dinâmico por Classificação
CIRC2-Lance - 005 | 0.330787 | 1120 | 5160.33 | 2510.33 | 4.89426 | 1569.11 | 5060.33 | 2410.33 | 4360.57 | 1710.57 | 0 | 699.762 | Estrutura de Escada - 005
CIRC2-Lance - 007 | 0.3772 | 975 | 4213.81 | 1563.81 | 5.38476 | 1936.29 | 4290.57 | 1640.57 | 3330 | 680 | -762.667 | 960.571 | Estrutura de Escada - 007
CIRC2-Lance - 005 | 0.277421 | 1120 | 3147.5 | 497.5 | 4.1049 | 977.679 | 3230 | 580 | 2600 | -50 | -1787.5 | 630 | Estrutura de Escada - 005

# IfcRailing, CIRC2-GC-002
In: Segundo Pavimento
Classification: 3E 08 04 10 Guarda-corpo (NBR 15965-5 3E); Guarda-Corpo (Classificação ARCHICAD)
AC_Pset_RenovationAndPhasing - Renovation Status: Existing
ArchiCADQuantities - Área: 0.890184; Altura: 1250; Volume (Líquido): 1.19699; Elevação à Origem do Projeto: 3150; Elevação ao 1º Nível de Referência: 3150; Elevação ao 2º Nível de Referência: 3150; Elevação ao Nível do Mar: 3150; Elevação ao Piso: 500; Afastamento da Origem: 500; Comprimento 3D: 4688.4; Elevação do Topo ao Primeiro Nível de Referência: 5430.57; Elevação do Topo Ao Piso de Origem: 2780.57; Elevação do Topo À Cota Zero: 5430.57; Elevação do Topo Ao Nível do Mar: 5430.57; Elevação do Topo Ao Segundo Nível de Referência: 5430.57; Elevação da Base Ao Primeiro Nível de Referência: 3150; Elevação da Base Ao Piso de Origem: 500; Elevação da Base À Cota Zero: 3150; Elevação da Base Ao Nível do Mar: 3150; Elevação da Base Ao Segundo Nível de Referência: 3150; Área da Superfície do Topo (Líquida): 0.890184; Número de Balaústres: 0; Número de Corrimãos: 0; Número de Postes Internos: 0; Número de Painéis: 0; Número de Postes: 4; Número de Barras: 0; Número de Barras Superiores: 3; Comprimento Horizontal da Linha de Referência: 4340
BaseQuantities - Length: 4688.4; GrossVolume: 1.19699; NetVolume: 1.19699
EXPRESSÕES DE TEXTO (Expressão) - ID Dinâmico por Classificação: Guarda-Corpo -002; Localização do Produto no Projeto: Projeto: CECAP GuarulhosLocal: Piso: Segundo Pavimento Cômodo:
FABRICAÇÃO - Data de Fabricação: DD/MM/YYYY; Site do Produto: www.graphisoft.com
INFORMAÇÕES DO PRODUTO - Data de Aquisição: DD/MM/YYYY
Pset_ManufacturerTypeInformation - ProductionYear: DD/MM/YYYY
Pset_RailingCommon - IsExternal: yes

# IfcSlab: Concreto Armado Moldado in Loco - Estrutural 100 (9)
In: Segundo Pavimento
Type - PredefinedType: FLOOR; Material: Concreto Armado Moldado in Loco - Estrutural 100 mm
Classification: Laje (Classificação ARCHICAD); 3E 12 06 08 Laje (NBR 15965-5 3E)
AC_Pset_RenovationAndPhasing - Renovation Status: Existing
ArchiCADQuantities - Altura: 100; Área de Superfície dos Furos: 0; Espessura: 100; Perímetro Furos da Planta: 0
BaseQuantities - Width: 100
ESTRUTURA (Expressão) - Custo por Volume (m3): 0; Estimativa de Custo Total por Volume: 0; Estimativa de Custo Total por Volume (R$): 0,00 R$
PISOS (Expressão) - Índice de Perda (%): 10
SUPERFÍCIES (Mapas) - Superfície do Topo (Geral): Concreto - 03; Superfície da Base (Geral): Concreto - 03; Superfície da Face (Geral): Concreto - 03
Pset_SlabCommon - IsExternal: yes; LoadBearing: yes
Name | Área = Área da Superfície = Área da Superfície do Topo (Líquida) = Área da Superfície da Base (Líquida) = Área da Superfície do Topo (Bruta) = Área da Superfície do Topo (Condicional) = Área da Superfície da Base (Condicional) = Área da Superfície da Base (Bruta) = Área da Superfície do Topo da Laje (Condicional) = Área da Superfície da Base da Laje (Bruta) = Área da Superfície da Base da Laje (Bruta, com os furos) = Área da Superfície do Topo da Laje (Bruta) = Área da Superfície do Topo da Laje (Bruta, com os furos) = GrossArea = NetArea = Área da Superfície do Topo (Geral) = Área da Superfície da Base (Geral) = Área Condicional da Superfície do Topo (Geral) = Área Condicional da Superfície da Base (Geral) | Volume (Líquido) = Volume (Condicional) = Volume (Bruto) = GrossVolume = NetVolume | Elevação à Origem do Projeto = Elevação ao 1º Nível de Referência = Elevação ao 2º Nível de Referência = Elevação ao Nível do Mar | Elevação ao Piso = Afastamento da Origem | Elevação do Topo ao Primeiro Nível de Referência = Elevação do Topo À Cota Zero = Elevação do Topo Ao Nível do Mar = Elevação do Topo Ao Segundo Nível de Referência = Topo da Elevação | Elevação do Topo Ao Piso de Origem | Elevação da Base Ao Primeiro Nível de Referência = Elevação da Base À Cota Zero = Elevação da Base Ao Nível do Mar = Elevação da Base Ao Segundo Nível de Referência = Elevação da Base | Elevação da Base Ao Piso de Origem | Perímetro na Planta = Perimeter | Área da Superfície da Borda (Líquida) = Área da Superfície das Bordas (Bruta) = Área da Superfície das Bordas da Laje (Bruta) = Área da Superfície das Bordas da Laje (Bruta, com as bordas dos furos) = Área da Superfície da Face (Geral) | ID Dinâmico por Classificação
APTO5-LAJE-001 | 3.5598 | 0.35598 | 2750 | 100 | 2750 | 100 | 2650 | 3.55271e-12 | 14980 | 1.498 | Laje -001
APTO5-LAJE-004 | 2.856 | 0.2856 | 2750 | 100 | 2750 | 100 | 2650 | 3.55271e-12 | 12220 | 1.222 | Laje -004
APTO6-LAJE-001 | 3.5598 | 0.35598 | 2750 | 100 | 2750 | 100 | 2650 | 3.55271e-12 | 14980 | 1.498 | Laje -001
APTO6-LAJE-004 | 2.856 | 0.2856 | 2750 | 100 | 2750 | 100 | 2650 | 3.55271e-12 | 12220 | 1.222 | Laje -004
APTO7-LAJE-001 | 3.5598 | 0.35598 | 2750 | 100 | 2750 | 100 | 2650 | 3.55271e-12 | 14980 | 1.498 | Laje -001
APTO7-LAJE-004 | 2.856 | 0.2856 | 2750 | 100 | 2750 | 100 | 2650 | 3.55271e-12 | 12220 | 1.222 | Laje -004
APTO8-LAJE-001 | 3.5598 | 0.35598 | 2750 | 100 | 2750 | 100 | 2650 | 3.55271e-12 | 14980 | 1.498 | Laje -001
APTO8-LAJE-004 | 2.856 | 0.2856 | 2750 | 100 | 2750 | 100 | 2650 | 3.55271e-12 | 12220 | 1.222 | Laje -004
CIRC2-LAJE-007 | 20.0831 | 2.00831 | 2500 | -150 | 2600 | -50 | 2500 | -150 | 28540 | 2.854 | Laje -007

# IfcSlab: Concreto Armado Moldado in Loco - Estrutural 120 (8)
In: Segundo Pavimento
Type - PredefinedType: FLOOR; Material: Concreto Armado Moldado in Loco - Estrutural 120 mm
Classification: Laje (Classificação ARCHICAD); 3E 12 06 08 Laje (NBR 15965-5 3E)
AC_Pset_RenovationAndPhasing - Renovation Status: Existing
ArchiCADQuantities - Altura: 120; Elevação à Origem do Projeto: 4005; Elevação ao 1º Nível de Referência: 4005; Elevação ao 2º Nível de Referência: 4005; Elevação ao Nível do Mar: 4005; Elevação ao Piso: 1355; Afastamento da Origem: 1355; Elevação do Topo ao Primeiro Nível de Referência: 4005; Elevação do Topo Ao Piso de Origem: 1355; Elevação do Topo À Cota Zero: 4005; Elevação do Topo Ao Nível do Mar: 4005; Elevação do Topo Ao Segundo Nível de Referência: 4005; Elevação da Base Ao Primeiro Nível de Referência: 3885; Elevação da Base Ao Piso de Origem: 1235; Elevação da Base À Cota Zero: 3885; Elevação da Base Ao Nível do Mar: 3885; Elevação da Base Ao Segundo Nível de Referência: 3885; Área de Superfície dos Furos: 0; Espessura: 120; Perímetro Furos da Planta: 0; Elevação da Base: 3885; Topo da Elevação: 4005
BaseQuantities - Width: 120
ESTRUTURA (Expressão) - Custo por Volume (m3): 0; Estimativa de Custo Total por Volume: 0; Estimativa de Custo Total por Volume (R$): 0,00 R$
PISOS (Expressão) - Índice de Perda (%): 10
SUPERFÍCIES (Mapas) - Superfície do Topo (Geral): Concreto - 03; Superfície da Base (Geral): Concreto - 03; Superfície da Face (Geral): Concreto - 03
Pset_SlabCommon - IsExternal: yes; LoadBearing: yes
Name | Área = Área da Superfície = Área da Superfície do Topo (Líquida) = Área da Superfície da Base (Líquida) = Área da Superfície do Topo (Bruta) = Área da Superfície do Topo (Condicional) = Área da Superfície da Base (Condicional) = Área da Superfície da Base (Bruta) = Área da Superfície do Topo da Laje (Condicional) = Área da Superfície da Base da Laje (Bruta) = Área da Superfície da Base da Laje (Bruta, com os furos) = Área da Superfície do Topo da Laje (Bruta) = Área da Superfície do Topo da Laje (Bruta, com os furos) = GrossArea = NetArea = Área da Superfície do Topo (Geral) = Área da Superfície da Base (Geral) = Área Condicional da Superfície do Topo (Geral) = Área Condicional da Superfície da Base (Geral) | Volume (Líquido) = Volume (Condicional) = Volume (Bruto) = GrossVolume = NetVolume | Perímetro na Planta = Perimeter | Área da Superfície da Borda (Líquida) = Área da Superfície das Bordas (Bruta) = Área da Superfície das Bordas da Laje (Bruta) = Área da Superfície das Bordas da Laje (Bruta, com as bordas dos furos) = Área da Superfície da Face (Geral) | ID Dinâmico por Classificação
APTO5-LAJE-003 | 2.856 | 0.34272 | 12220 | 1.4664 | Laje -003
APTO5-LAJE-002 | 3.5598 | 0.427176 | 14980 | 1.7976 | Laje -002
APTO6-LAJE-003 | 2.856 | 0.34272 | 12220 | 1.4664 | Laje -003
APTO6-LAJE-002 | 3.5598 | 0.427176 | 14980 | 1.7976 | Laje -002
APTO7-LAJE-003 | 2.856 | 0.34272 | 12220 | 1.4664 | Laje -003
APTO7-LAJE-002 | 3.5598 | 0.427176 | 14980 | 1.7976 | Laje -002
APTO8-LAJE-003 | 2.856 | 0.34272 | 12220 | 1.4664 | Laje -003
APTO8-LAJE-002 | 3.5598 | 0.427176 | 14980 | 1.7976 | Laje -002

# IfcSlab: Concreto Armado Moldado in Loco - Estrutural 150 (4)
In: Segundo Pavimento
Type - PredefinedType: FLOOR; Material: Concreto Armado Moldado in Loco - Estrutural 150 mm
Classification: Laje (Classificação ARCHICAD); 3E 12 06 08 Laje (NBR 15965-5 3E)
AC_Pset_RenovationAndPhasing - Renovation Status: Existing
ArchiCADQuantities - Área: 58.5617; Altura: 150; Volume (Líquido): 8.78425; Elevação à Origem do Projeto: 2650; Elevação ao 1º Nível de Referência: 2650; Elevação ao 2º Nível de Referência: 2650; Elevação ao Nível do Mar: 2650; Elevação ao Piso: 0; Afastamento da Origem: 0; Área da Superfície: 58.5617; Volume (Condicional): 8.78425; Volume (Bruto): 8.82475; Elevação do Topo ao Primeiro Nível de Referência: 2650; Elevação do Topo Ao Piso de Origem: 0; Elevação do Topo À Cota Zero: 2650; Elevação do Topo Ao Nível do Mar: 2650; Elevação do Topo Ao Segundo Nível de Referência: 2650; Elevação da Base Ao Primeiro Nível de Referência: 2500; Elevação da Base Ao Piso de Origem: -150; Elevação da Base À Cota Zero: 2500; Elevação da Base Ao Nível do Mar: 2500; Elevação da Base Ao Segundo Nível de Referência: 2500; Área da Superfície do Topo (Líquida): 58.5617; Área da Superfície da Base (Líquida): 58.5617; Área de Superfície dos Furos: 0.27; Área da Superfície do Topo (Bruta): 58.8317; Espessura: 150; Perímetro na Planta: 30770; Área da Superfície da Borda (Líquida): 4.4355; Perímetro Furos da Planta: 0; Área da Superfície do Topo (Condicional): 58.5617; Área da Superfície da Base (Condicional): 58.5617; Área da Superfície da Base (Bruta): 58.8317; Área da Superfície das Bordas (Bruta): 4.6155; Elevação da Base: 2500; Área da Superfície do Topo da Laje (Condicional): 58.5617; Área da Superfície da Base da Laje (Bruta): 58.8317; Área da Superfície da Base da Laje (Bruta, com os furos): 58.8317; Área da Superfície das Bordas da Laje (Bruta): 4.6155; Área da Superfície das Bordas da Laje (Bruta, com as bordas dos furos): 4.6155; Área da Superfície do Topo da Laje (Bruta): 58.8317; Área da Superfície do Topo da Laje (Bruta, com os furos): 58.8317; Topo da Elevação: 2650
BaseQuantities - Width: 150; GrossVolume: 8.82475; NetVolume: 8.78425; Perimeter: 30770; GrossArea: 58.8317; NetArea: 58.5617
ESTRUTURA (Expressão) - Custo por Volume (m3): 0; Estimativa de Custo Total por Volume: 0; Estimativa de Custo Total por Volume (R$): 0,00 R$
EXPRESSÕES DE TEXTO (Expressão) - ID Dinâmico por Classificação: Laje -000
PISOS (Expressão) - Índice de Perda (%): 10
SUPERFÍCIES (Mapas) - Superfície do Topo (Geral): Concreto - 03; Superfície da Base (Geral): Concreto - 03; Área da Superfície do Topo (Geral): 58.5617; Área da Superfície da Base (Geral): 58.5617; Superfície da Face (Geral): Concreto - 03; Área da Superfície da Face (Geral): 4.4355; Área Condicional da Superfície do Topo (Geral): 58.5617; Área Condicional da Superfície da Base (Geral): 58.5617
Pset_SlabCommon - IsExternal: no; LoadBearing: yes
Name
APTO5-LAJE-000
APTO6-LAJE-000
APTO7-LAJE-000
APTO8-LAJE-000

# IfcSlab: Concreto Armado Moldado in Loco - Estrutural 180 (2)
In: Segundo Pavimento
Type - PredefinedType: FLOOR; Material: Concreto Armado Moldado in Loco - Estrutural 180 mm
Classification: Laje (Classificação ARCHICAD); 3E 08 06 04 06 Patamar de escada (NBR 15965-5 3E)
AC_Pset_RenovationAndPhasing - Renovation Status: Existing
ArchiCADQuantities - Altura: 180; Área de Superfície dos Furos: 0; Espessura: 180; Perímetro na Planta: 5550; Área da Superfície da Borda (Líquida): 0.999; Perímetro Furos da Planta: 0; Área da Superfície das Bordas (Bruta): 0.999; Área da Superfície das Bordas da Laje (Bruta): 0.999; Área da Superfície das Bordas da Laje (Bruta, com as bordas dos furos): 0.999
BaseQuantities - Width: 180; Perimeter: 5550
ESTRUTURA (Expressão) - Custo por Volume (m3): 0; Estimativa de Custo Total por Volume: 0; Estimativa de Custo Total por Volume (R$): 0,00 R$
PISOS (Expressão) - Índice de Perda (%): 10
SUPERFÍCIES (Mapas) - Superfície do Topo (Geral): Concreto - 03; Superfície da Base (Geral): Concreto - 03; Superfície da Face (Geral): Concreto - 03; Área da Superfície da Face (Geral): 0.999
Pset_SlabCommon - IsExternal: yes; LoadBearing: yes
Name | Área = Área da Superfície = Área da Superfície do Topo (Líquida) = Área da Superfície da Base (Líquida) = Área da Superfície do Topo (Bruta) = Área da Superfície do Topo (Condicional) = Área da Superfície da Base (Condicional) = Área da Superfície da Base (Bruta) = Área da Superfície do Topo da Laje (Condicional) = Área da Superfície da Base da Laje (Bruta) = Área da Superfície da Base da Laje (Bruta, com os furos) = Área da Superfície do Topo da Laje (Bruta) = Área da Superfície do Topo da Laje (Bruta, com os furos) = GrossArea = NetArea = Área da Superfície do Topo (Geral) = Área da Superfície da Base (Geral) = Área Condicional da Superfície do Topo (Geral) = Área Condicional da Superfície da Base (Geral) | Volume (Líquido) = Volume (Condicional) = Volume (Bruto) = GrossVolume = NetVolume | Elevação à Origem do Projeto = Elevação ao 1º Nível de Referência = Elevação ao 2º Nível de Referência = Elevação ao Nível do Mar = Elevação do Topo ao Primeiro Nível de Referência = Elevação do Topo À Cota Zero = Elevação do Topo Ao Nível do Mar = Elevação do Topo Ao Segundo Nível de Referência = Topo da Elevação | Elevação ao Piso = Afastamento da Origem = Elevação do Topo Ao Piso de Origem | Elevação da Base Ao Primeiro Nível de Referência = Elevação da Base À Cota Zero = Elevação da Base Ao Nível do Mar = Elevação da Base Ao Segundo Nível de Referência = Elevação da Base | Elevação da Base Ao Piso de Origem | ID Dinâmico por Classificação
CIRC2-LAJE-005 | 1.86635 | 0.335943 | 4360.57 | 1710.57 | 4180.57 | 1530.57 | Laje -005
CIRC2-LAJE-006 | 1.8188 | 0.327384 | 3330 | 680 | 3150 | 500 | Laje -006

# IfcStair (3)
In: Segundo Pavimento
Classification: Escada (Classificação ARCHICAD); 3E 08 06 04 Escada (NBR 15965-5 3E)
AC_Pset_RenovationAndPhasing - Renovation Status: Existing
ArchiCADQuantities - Largura Piso Padrão: 270; Dimensão da Altura Livre Obrigatória: 2200; Piso Mínimo (pela Regra): 270; Piso Máximo (pela Regra): 270
DESCRIÇÃO DA ESCADA (Expressão) - Abreviação da Largura da Escada: L; Abreviação da Altura do Espelho: E; Abreviação da Profundidade do Piso: P
EXPRESSÕES DE TEXTO (Expressão) - Localização do Produto no Projeto: Projeto: CECAP GuarulhosLocal: Piso: Segundo Pavimento Cômodo: ESCADA
Pset_StairCommon - RequiredHeadroom: 2200 mm; IsExternal: yes
Name | Área = Área da Superfície do Topo (Líquida) | Altura = Height | Volume (Líquido) = GrossVolume = NetVolume | Elevação à Origem do Projeto = Elevação ao 1º Nível de Referência = Elevação ao 2º Nível de Referência = Elevação ao Nível do Mar = Elevação da Base Ao Primeiro Nível de Referência = Elevação da Base À Cota Zero = Elevação da Base Ao Nível do Mar = Elevação da Base Ao Segundo Nível de Referência | Elevação ao Piso = Afastamento da Origem = Elevação da Base Ao Piso de Origem | Elevação do Topo ao Primeiro Nível de Referência = Elevação do Topo À Cota Zero = Elevação do Topo Ao Nível do Mar = Elevação do Topo Ao Segundo Nível de Referência | Elevação do Topo Ao Piso de Origem | Afastamento do Topo | Altura do Espelho Padrão = RiserHeight (mm) | Largura da Escada Padrão | Área de Superfície Frontal da Escada | Altura Máxima do Espelho (pela Regra) | Número De Espelhos (total) = NumberOfRiser | Número De Pisos (total) = NumberOfTreads | Comprimento Linha de Subida = Length | Info 2E + P | Resultado 2E + P | ID Dinâmico por Classificação | Altura Mínima do Espelho (pela Regra)
CIRC2-ESCADA-002 | 1.512 | 799.762 | 0.330787 | 4360.57 | 1710.57 | 5060.33 | 2410.33 | 0 | 159.952 | 1120 | 1.03573 | 180 | 5 | 5 | 1350 | 2 x 0,16 ( E ) + 0,27 ( P ) = 0,59 | 589.905 | Escada -002
CIRC2-ESCADA-000 | 1.5795 | 1060.57 | 0.3772 | 3330 | 680 | 4290.57 | 1640.57 | -939.429 | 176.762 | 975 | 1.18031 | 180 | 6 | 6 | 1620 | 2 x 0,18 ( E ) + 0,27 ( P ) = 0,62 | 623.524 | Escada -000 | 170
CIRC2-ESCADA-001 | 0.9072 | 730 | 0.277421 | 2600 | -50 | 3230 | 580 | -1970 | 182.5 | 1120 | 0.9016 |  | 4 | 3 | 810 | 2 x 0,18 ( E ) + 0,27 ( P ) = 0,64 | 635 | Escada -001 | 170

# IfcWall: GC - Barra Superior - 001, CIRC2-GC - Barra Superior - 001
In: Segundo Pavimento
Classification: Parede (Classificação ARCHICAD); Material: Concreto
AC_Pset_RenovationAndPhasing - Renovation Status: Existing
ALVENARIAS (Expressão) - Espessura da Argamassa: 10
ArchiCADQuantities - Altura: 1250; Volume (Líquido): 0.40139; Largura: 205.112; Elevação à Origem do Projeto: 4400; Elevação ao 1º Nível de Referência: 4400; Elevação ao 2º Nível de Referência: 4400; Elevação ao Nível do Mar: 4400; Elevação ao Piso: 1750; Afastamento da Origem: 1750; Comprimento 3D: 1782.59; Elevação do Topo ao Primeiro Nível de Referência: 4400; Elevação do Topo Ao Piso de Origem: 1750; Elevação do Topo À Cota Zero: 4400; Elevação do Topo Ao Nível do Mar: 4400; Elevação do Topo Ao Segundo Nível de Referência: 4400; Elevação da Base Ao Primeiro Nível de Referência: 3150; Elevação da Base Ao Piso de Origem: 500; Elevação da Base À Cota Zero: 3150; Elevação da Base Ao Nível do Mar: 3150; Elevação da Base Ao Segundo Nível de Referência: 3150; Espessura: 205.112
BaseQuantities - Length: 1782.59; GrossVolume: 0.40139; NetVolume: 0.40139
EXPRESSÕES DE TEXTO (Expressão) - ID Dinâmico por Classificação: Parede - Barra Superior - 001

# IfcWall: GC - Barra Superior - 001_1, CIRC2-GC - Barra Superior - 001
In: Segundo Pavimento
Classification: Parede (Classificação ARCHICAD); Material: Concreto
AC_Pset_RenovationAndPhasing - Renovation Status: Existing
ALVENARIAS (Expressão) - Espessura da Argamassa: 10
ArchiCADQuantities - Altura: 1250; Volume (Líquido): 0.433619; Largura: 205.112; Elevação à Origem do Projeto: 5430.57; Elevação ao 1º Nível de Referência: 5430.57; Elevação ao 2º Nível de Referência: 5430.57; Elevação ao Nível do Mar: 5430.57; Elevação ao Piso: 2780.57; Afastamento da Origem: 2780.57; Comprimento 3D: 2120.99; Elevação do Topo ao Primeiro Nível de Referência: 5430.57; Elevação do Topo Ao Piso de Origem: 2780.57; Elevação do Topo À Cota Zero: 5430.57; Elevação do Topo Ao Nível do Mar: 5430.57; Elevação do Topo Ao Segundo Nível de Referência: 5430.57; Elevação da Base Ao Primeiro Nível de Referência: 3150; Elevação da Base Ao Piso de Origem: 500; Elevação da Base À Cota Zero: 3150; Elevação da Base Ao Nível do Mar: 3150; Elevação da Base Ao Segundo Nível de Referência: 3150; Espessura: 205.112
BaseQuantities - Length: 2120.99; GrossVolume: 0.433619; NetVolume: 0.433619
EXPRESSÕES DE TEXTO (Expressão) - ID Dinâmico por Classificação: Parede - Barra Superior - 001

# IfcWall: GC - Barra Superior - 001_3, CIRC2-GC - Barra Superior - 001
In: Segundo Pavimento
Classification: Parede (Classificação ARCHICAD); Material: Concreto
AC_Pset_RenovationAndPhasing - Renovation Status: Existing
ALVENARIAS (Expressão) - Espessura da Argamassa: 10
ArchiCADQuantities - Altura: 1250; Volume (Líquido): 0.361985; Largura: 205.112; Elevação à Origem do Projeto: 5430.57; Elevação ao 1º Nível de Referência: 5430.57; Elevação ao 2º Nível de Referência: 5430.57; Elevação ao Nível do Mar: 5430.57; Elevação ao Piso: 2780.57; Afastamento da Origem: 2780.57; Comprimento 3D: 1630; Elevação do Topo ao Primeiro Nível de Referência: 5430.57; Elevação do Topo Ao Piso de Origem: 2780.57; Elevação do Topo À Cota Zero: 5430.57; Elevação do Topo Ao Nível do Mar: 5430.57; Elevação do Topo Ao Segundo Nível de Referência: 5430.57; Elevação da Base Ao Primeiro Nível de Referência: 4180.57; Elevação da Base Ao Piso de Origem: 1530.57; Elevação da Base À Cota Zero: 4180.57; Elevação da Base Ao Nível do Mar: 4180.57; Elevação da Base Ao Segundo Nível de Referência: 4180.57; Espessura: 205.112
BaseQuantities - Length: 1630; GrossVolume: 0.361985; NetVolume: 0.361985
EXPRESSÕES DE TEXTO (Expressão) - ID Dinâmico por Classificação: Parede - Barra Superior - 001

# IfcWallStandardCase: Concreto Armado Moldado in Loco - Estrutural 190 (3)
In: Segundo Pavimento
Type - PredefinedType: STANDARD; Material: Concreto Armado Moldado in Loco - Estrutural 190 mm
Classification: Parede (Classificação ARCHICAD); 3E 14 02 00 Parede (NBR 15965-5 3E)
AC_Pset_RenovationAndPhasing - Renovation Status: Existing
ALVENARIAS (Expressão) - Espessura da Argamassa: 10
ArchiCADQuantities - Altura: 2700; Largura: 190; Elevação à Origem do Projeto: 2600; Elevação ao 1º Nível de Referência: 2600; Elevação ao 2º Nível de Referência: 2600; Elevação ao Nível do Mar: 2600; Elevação ao Piso: -50; Afastamento da Origem: -50; Elevação do Topo ao Primeiro Nível de Referência: 5250; Elevação do Topo Ao Piso de Origem: 2600; Elevação do Topo À Cota Zero: 5250; Elevação do Topo Ao Nível do Mar: 5250; Elevação do Topo Ao Segundo Nível de Referência: 5250; Elevação da Base Ao Primeiro Nível de Referência: 2600; Elevação da Base Ao Piso de Origem: -50; Elevação da Base À Cota Zero: 2600; Elevação da Base Ao Nível do Mar: 2600; Elevação da Base Ao Segundo Nível de Referência: 2600; Afastamento do Topo: 0; Espessura: 190; Espessura da Camada de Isolamento: 0; Número de Portas: 0; Número de Furos (Número de Aberturas Vazias): 0; Número de Janelas: 0; Número de Pilares: 0; Volume dos Pilares: 0; Altura Máxima da Camada da Parede na Face Interna: 0; Altura Mínima da Camada da Parede na Face Interna: 0; Altura máxima da parede: 2650; Altura mínima da parede: 0; Altura Máxima da Camada da Parede na Face Externa: 0; Altura Mínima da Camada da Parede na Face Externa: 0; Espessura da Camada de Ar: 0; Área das Portas: 0; Soma das Larguras das Portas: 0; Espessura do Componente na Face Interna da Parede: 0; Espessura do Componentena na Face Externa da Parede: 0; Área das Janelas: 0; Soma das Larguras das Janelas: 0; Área Analítica da Superfície das Aberturas da Face Interna: 0; Área Analítica da Superfície das Aberturas da Face Externa: 0; Volume Analítico das Aberturas: 0; Espessura da Parede na Terminação: 190; Área de Superfície do Vão na Parede: 0
BaseQuantities - Width: 190; Height: 2650
CLASSIFICAÇÕES GERAIS - Transmissão Sonora: 0
SUPERFÍCIES (Mapas) - Superfície da Face (Geral): Concreto - 03
Pset_WallCommon - AcousticRating: 0,00; IsExternal: yes
Name | Área = Área da Superfície do Topo (Líquida) = GrossFootprintArea = NetFootprintArea | Volume (Líquido) = Volume (Condicional) = GrossVolume = NetVolume | Área da Superfície = Área da Superfície da Base (Líquida) = Área da Superfície da Face Externa da Parede (Líquida) = Área da Superfície da Face Externa da Parede (Condicional) | Comprimento 3D | Volume (Bruto) | Perímetro na Planta | Área da Superfície da Borda (Líquida) = Área da Superfície da Face (Geral) | Comprimento Médio da Parede = Comprimento da parede no centro = Length | Área da Superfície da Face Interna da Parede (Líquida) = Área da Superfície da Face Interna da Parede (Condicional) | Comprimento da Linha de Referência = Comprimento da Face Externa da Parede (Condicional) = Comprimento da Parede na Face Externa | Comprimento da Face Interna da Parede (Condicional) = Comprimento da Parede na Face Interna | Área da Superfície da Face Interna da Parede (Bruta) = Área da Superfície da Face Externa da Parede (Bruta) | GrossSideArea = NetSideArea | ID Dinâmico por Classificação
CIRC2-PAREDE-022 | 0.3629 | 0.951893 | 5.0615 | 1910 | 1.0773 | 4357.4 | 0.3629 | 1910 | 5.0039 | 1720 | 2100 | 5.67 | 5.0327 | Parede -022
CIRC2-PAREDE-023 | 0.2014 | 0.53371 | 2.809 | 1060 | 0.64125 | 2768.7 | 0.7049 | 1155 | 2.809 | 1060 | 1250 | 3.375 | 2.809 | Parede -023
CIRC2-PAREDE-024 | 0.2375 | 0.623561 | 3.2819 | 1250 | 0.64125 | 2768.7 | 0.741 | 1155 | 3.2819 | 1060 | 1250 | 3.375 | 3.2819 | Parede -024

# IfcWallStandardCase: Concreto Armado Moldado in Loco - Estrutural 50 (16)
In: Segundo Pavimento
Type - PredefinedType: STANDARD; Material: Concreto Armado Moldado in Loco - Estrutural 50 mm
Classification: Parede (Classificação ARCHICAD); 3E 14 02 00 Parede (NBR 15965-5 3E)
AC_Pset_RenovationAndPhasing - Renovation Status: Existing
ALVENARIAS (Expressão) - Espessura da Argamassa: 10
ArchiCADQuantities - Área: 0.0215; Altura: 1270; Volume (Líquido): 0.0244025; Largura: 50; Elevação à Origem do Projeto: 2650; Elevação ao 1º Nível de Referência: 2650; Elevação ao 2º Nível de Referência: 2650; Elevação ao Nível do Mar: 2650; Elevação ao Piso: 0; Afastamento da Origem: 0; Área da Superfície: 0.48805; Comprimento 3D: 430; Volume (Condicional): 0.0244025; Elevação do Topo ao Primeiro Nível de Referência: 3885; Elevação do Topo Ao Piso de Origem: 1235; Elevação do Topo À Cota Zero: 3885; Elevação do Topo Ao Nível do Mar: 3885; Elevação do Topo Ao Segundo Nível de Referência: 3885; Elevação da Base Ao Primeiro Nível de Referência: 2750; Elevação da Base Ao Piso de Origem: 100; Elevação da Base À Cota Zero: 2750; Elevação da Base Ao Nível do Mar: 2750; Elevação da Base Ao Segundo Nível de Referência: 2750; Área da Superfície do Topo (Líquida): 0.0215; Área da Superfície da Base (Líquida): 0.48805; Afastamento do Topo: -1380; Espessura: 50; Espessura da Camada de Isolamento: 0; Área da Superfície da Borda (Líquida): 0.05675; Número de Portas: 0; Número de Furos (Número de Aberturas Vazias): 0; Número de Janelas: 0; Número de Pilares: 0; Volume dos Pilares: 0; Altura Máxima da Camada da Parede na Face Interna: 0; Altura Mínima da Camada da Parede na Face Interna: 0; Altura máxima da parede: 1135; Altura mínima da parede: 0; Altura Máxima da Camada da Parede na Face Externa: 0; Altura Mínima da Camada da Parede na Face Externa: 0; Espessura da Camada de Ar: 0; Área das Portas: 0; Soma das Larguras das Portas: 0; Espessura do Componente na Face Interna da Parede: 0; Espessura do Componentena na Face Externa da Parede: 0; Área das Janelas: 0; Soma das Larguras das Janelas: 0; Área Analítica da Superfície das Aberturas da Face Interna: 0; Área Analítica da Superfície das Aberturas da Face Externa: 0; Área da Superfície da Face Interna da Parede (Líquida): 0.48805; Área da Superfície da Face Externa da Parede (Líquida): 0.48805; Volume Analítico das Aberturas: 0; Área da Superfície da Face Interna da Parede (Condicional): 0.48805; Área da Superfície da Face Externa da Parede (Condicional): 0.48805; Espessura da Parede na Terminação: 50; Área de Superfície do Vão na Parede: 0
BaseQuantities - Width: 50; GrossVolume: 0.0244025; NetVolume: 0.0244025; Height: 1135; GrossFootprintArea: 0.0215; NetFootprintArea: 0.0215; GrossSideArea: 0.48805; NetSideArea: 0.48805
CLASSIFICAÇÕES GERAIS - Transmissão Sonora: 0
SUPERFÍCIES (Mapas) - Superfície da Face (Geral): Concreto - 03; Área da Superfície da Face (Geral): 0.05675
Pset_WallCommon - AcousticRating: 0,00; IsExternal: yes
Name | Volume (Bruto) | Perímetro na Planta | Comprimento Médio da Parede = Comprimento da parede no centro = Length | Comprimento da Linha de Referência = Comprimento da Face Externa da Parede (Condicional) = Comprimento da Parede na Face Externa | Comprimento da Face Interna da Parede (Condicional) = Comprimento da Parede na Face Interna | Área da Superfície da Face Interna da Parede (Bruta) = Área da Superfície da Face Externa da Parede (Bruta) | ID Dinâmico por Classificação
APTO5-PAREDE-016 | 0.0276225 | 970 | 435 | 435 | 435 | 0.55245 | Parede -016
APTO5-PAREDE-018 | 0.032385 | 1084.34 | 470 | 430 | 510 | 0.6477 | Parede -018
APTO5-PAREDE-002 | 0.032385 | 1084.34 | 470 | 430 | 510 | 0.6477 | Parede -002
APTO5-PAREDE-001 | 0.0276225 | 970 | 435 | 435 | 435 | 0.55245 | Parede -001
APTO6-PAREDE-016 | 0.0276225 | 970 | 435 | 435 | 435 | 0.55245 | Parede -016
APTO6-PAREDE-018 | 0.032385 | 1084.34 | 470 | 430 | 510 | 0.6477 | Parede -018
APTO6-PAREDE-002 | 0.032385 | 1084.34 | 470 | 430 | 510 | 0.6477 | Parede -002
APTO6-PAREDE-001 | 0.0276225 | 970 | 435 | 435 | 435 | 0.55245 | Parede -001
APTO7-PAREDE-016 | 0.0276225 | 970 | 435 | 435 | 435 | 0.55245 | Parede -016
APTO7-PAREDE-018 | 0.032385 | 1084.34 | 470 | 430 | 510 | 0.6477 | Parede -018
APTO7-PAREDE-002 | 0.032385 | 1084.34 | 470 | 430 | 510 | 0.6477 | Parede -002
APTO7-PAREDE-001 | 0.0276225 | 970 | 435 | 435 | 435 | 0.55245 | Parede -001
APTO8-PAREDE-016 | 0.0276225 | 970 | 435 | 435 | 435 | 0.55245 | Parede -016
APTO8-PAREDE-018 | 0.032385 | 1084.34 | 470 | 430 | 510 | 0.6477 | Parede -018
APTO8-PAREDE-002 | 0.032385 | 1084.34 | 470 | 430 | 510 | 0.6477 | Parede -002
APTO8-PAREDE-001 | 0.0276225 | 970 | 435 | 435 | 435 | 0.55245 | Parede -001

# IfcWallStandardCase: Concreto Armado Moldado in Loco - Estrutural 80 (8)
In: Segundo Pavimento
Type - PredefinedType: STANDARD; Material: Concreto Armado Moldado in Loco - Estrutural 80 mm
Classification: Parede (Classificação ARCHICAD); 3E 14 02 00 Parede (NBR 15965-5 3E)
AC_Pset_RenovationAndPhasing - Renovation Status: Existing
ALVENARIAS (Expressão) - Espessura da Argamassa: 10
ArchiCADQuantities - Altura: 1765; Largura: 80; Elevação à Origem do Projeto: 2200; Elevação ao 1º Nível de Referência: 2200; Elevação ao 2º Nível de Referência: 2200; Elevação ao Nível do Mar: 2200; Elevação ao Piso: -450; Afastamento da Origem: -450; Elevação do Topo ao Primeiro Nível de Referência: 3885; Elevação do Topo Ao Piso de Origem: 1235; Elevação do Topo À Cota Zero: 3885; Elevação do Topo Ao Nível do Mar: 3885; Elevação do Topo Ao Segundo Nível de Referência: 3885; Elevação da Base Ao Primeiro Nível de Referência: 2200; Elevação da Base Ao Piso de Origem: -450; Elevação da Base À Cota Zero: 2200; Elevação da Base Ao Nível do Mar: 2200; Elevação da Base Ao Segundo Nível de Referência: 2200; Afastamento do Topo: 0; Espessura: 80; Espessura da Camada de Isolamento: 0; Número de Portas: 0; Número de Furos (Número de Aberturas Vazias): 0; Número de Janelas: 0; Número de Pilares: 0; Volume dos Pilares: 0; Altura Máxima da Camada da Parede na Face Interna: 0; Altura Mínima da Camada da Parede na Face Interna: 0; Altura máxima da parede: 1685; Altura mínima da parede: 0; Altura Máxima da Camada da Parede na Face Externa: 0; Altura Mínima da Camada da Parede na Face Externa: 0; Espessura da Camada de Ar: 0; Área das Portas: 0; Soma das Larguras das Portas: 0; Espessura do Componente na Face Interna da Parede: 0; Espessura do Componentena na Face Externa da Parede: 0; Área das Janelas: 0; Soma das Larguras das Janelas: 0; Área Analítica da Superfície das Aberturas da Face Interna: 0; Área Analítica da Superfície das Aberturas da Face Externa: 0; Volume Analítico das Aberturas: 0; Espessura da Parede na Terminação: 80; Área de Superfície do Vão na Parede: 0
BaseQuantities - Width: 80; Height: 1685
CLASSIFICAÇÕES GERAIS - Transmissão Sonora: 0
SUPERFÍCIES (Mapas) - Superfície da Face (Geral): Concreto - 03
Pset_WallCommon - AcousticRating: 0,00; IsExternal: yes
Name | Área = Área da Superfície do Topo (Líquida) = GrossFootprintArea = NetFootprintArea | Volume (Líquido) = Volume (Condicional) = GrossVolume = NetVolume | Área da Superfície = Área da Superfície da Base (Líquida) = Área da Superfície da Face Interna da Parede (Líquida) = Área da Superfície da Face Externa da Parede (Líquida) = Área da Superfície da Face Interna da Parede (Condicional) = Área da Superfície da Face Externa da Parede (Condicional) = GrossSideArea = NetSideArea | Comprimento 3D = Comprimento da Linha de Referência = Comprimento da Face Externa da Parede (Condicional) = Comprimento da Parede na Face Externa | Volume (Bruto) | Perímetro na Planta | Área da Superfície da Borda (Líquida) = Área da Superfície da Face (Geral) | Comprimento Médio da Parede = Comprimento da parede no centro = Length | Comprimento da Face Interna da Parede (Condicional) = Comprimento da Parede na Face Interna | Área da Superfície da Face Interna da Parede (Bruta) = Área da Superfície da Face Externa da Parede (Bruta) | ID Dinâmico por Classificação
APTO5-PAREDE-017 | 0.448 | 0.71008 | 8.876 | 5600 | 0.79072 | 11324.3 | 0.5748 | 5575 | 5550 | 9.884 | Parede -017
APTO5-PAREDE-015 | 0.5584 | 0.885064 | 11.0633 | 6980 | 0.985576 | 14084.3 | 0.6852 | 6955 | 6930 | 12.3197 | Parede -015
APTO6-PAREDE-017 | 0.448 | 0.71008 | 8.876 | 5600 | 0.79072 | 11324.3 | 0.5748 | 5575 | 5550 | 9.884 | Parede -017
APTO6-PAREDE-015 | 0.5584 | 0.885064 | 11.0633 | 6980 | 0.985576 | 14084.3 | 0.6852 | 6955 | 6930 | 12.3197 | Parede -015
APTO7-PAREDE-017 | 0.448 | 0.71008 | 8.876 | 5600 | 0.79072 | 11324.3 | 0.5748 | 5575 | 5550 | 9.884 | Parede -017
APTO7-PAREDE-015 | 0.5584 | 0.885064 | 11.0633 | 6980 | 0.985576 | 14084.3 | 0.6852 | 6955 | 6930 | 12.3197 | Parede -015
APTO8-PAREDE-017 | 0.448 | 0.71008 | 8.876 | 5600 | 0.79072 | 11324.3 | 0.5748 | 5575 | 5550 | 9.884 | Parede -017
APTO8-PAREDE-015 | 0.5584 | 0.885064 | 11.0633 | 6980 | 0.985576 | 14084.3 | 0.6852 | 6955 | 6930 | 12.3197 | Parede -015

# IfcWallStandardCase: GENÉRICO - VEDAÇÃO EXTERNA 140 (4)
In: Segundo Pavimento
Type - PredefinedType: STANDARD; Material: GENÉRICO - VEDAÇÃO EXTERNA 140 mm
Classification: Parede (Classificação ARCHICAD); 3E 14 02 00 Parede (NBR 15965-5 3E)
AC_Pset_RenovationAndPhasing - Renovation Status: Existing
ALVENARIAS (Expressão) - Espessura da Argamassa: 10
ArchiCADQuantities - Altura: 2200; Largura: 140; Elevação à Origem do Projeto: 2650; Elevação ao 1º Nível de Referência: 2650; Elevação ao 2º Nível de Referência: 2650; Elevação ao Nível do Mar: 2650; Elevação ao Piso: 0; Afastamento da Origem: 0; Elevação do Topo ao Primeiro Nível de Referência: 4850; Elevação do Topo Ao Piso de Origem: 2200; Elevação do Topo À Cota Zero: 4850; Elevação do Topo Ao Nível do Mar: 4850; Elevação do Topo Ao Segundo Nível de Referência: 4850; Elevação da Base Ao Primeiro Nível de Referência: 2650; Elevação da Base Ao Piso de Origem: 0; Elevação da Base À Cota Zero: 2650; Elevação da Base Ao Nível do Mar: 2650; Elevação da Base Ao Segundo Nível de Referência: 2650; Afastamento do Topo: -450; Espessura: 140; Espessura da Camada de Isolamento: 0; Perímetro na Planta: 3440; Número de Portas: 1; Número de Furos (Número de Aberturas Vazias): 0; Número de Janelas: 0; Número de Pilares: 0; Volume dos Pilares: 0; Altura Máxima da Camada da Parede na Face Interna: 0; Altura Mínima da Camada da Parede na Face Interna: 0; Altura máxima da parede: 2200; Altura Máxima da Camada da Parede na Face Externa: 0; Altura Mínima da Camada da Parede na Face Externa: 0; Espessura da Camada de Ar: 0; Área das Portas: 1.89; Soma das Larguras das Portas: 900; Espessura do Componente na Face Interna da Parede: 0; Espessura do Componentena na Face Externa da Parede: 0; Área das Janelas: 0; Soma das Larguras das Janelas: 0; Área Analítica da Superfície das Aberturas da Face Interna: 1.89; Área Analítica da Superfície das Aberturas da Face Externa: 1.89; Comprimento Médio da Parede: 1580; Volume Analítico das Aberturas: 0.2646; Comprimento da Linha de Referência: 1580; Comprimento da Face Interna da Parede (Condicional): 680; Comprimento da Face Externa da Parede (Condicional): 680; Espessura da Parede na Terminação: 140; Comprimento da parede no centro: 1580; Comprimento da Parede na Face Interna: 1580; Comprimento da Parede na Face Externa: 1580; Área de Superfície do Vão na Parede: 0
BaseQuantities - Length: 1580; Width: 140; Height: 2200
CLASSIFICAÇÕES GERAIS - Transmissão Sonora: 0
EXPRESSÕES DE TEXTO (Expressão) - ID Dinâmico por Classificação: Parede -004
SUPERFÍCIES (Mapas) - Superfície da Face (Geral): Pintura - Sienna Areia
Pset_WallCommon - AcousticRating: 0,00; IsExternal: yes
Name | Área = Área da Superfície do Topo (Líquida) = GrossFootprintArea = NetFootprintArea | Volume (Líquido) = NetVolume | Área da Superfície = Área da Superfície da Base (Líquida) = Área da Superfície da Face Interna da Parede (Líquida) = Área da Superfície da Face Externa da Parede (Líquida) = NetSideArea | Comprimento 3D | Volume (Condicional) = GrossVolume | Volume (Bruto) | Área da Superfície da Borda (Líquida) = Área da Superfície da Face (Geral) | Altura mínima da parede | Área da Superfície da Face Interna da Parede (Condicional) = Área da Superfície da Face Externa da Parede (Condicional) = GrossSideArea | Área da Superfície da Face Interna da Parede (Bruta) = Área da Superfície da Face Externa da Parede (Bruta)
APTO5-PAREDE-004 | 0.0686 | 0.16352 | 1.168 | 1390 | 0.42812 | 0.51744 | 0.5712 | 2100 | 3.058 | 3.696
APTO6-PAREDE-004 | 0.0952 | 0.22204 | 1.586 | 1580 | 0.48664 | 0.48664 | 0.9324 | 2200 | 3.476 | 3.476
APTO7-PAREDE-004 | 0.0686 | 0.16352 | 1.168 | 1390 | 0.42812 | 0.51744 | 0.5712 | 2100 | 3.058 | 3.696
APTO8-PAREDE-004 | 0.0952 | 0.22204 | 1.586 | 1580 | 0.48664 | 0.48664 | 0.9324 | 2200 | 3.476 | 3.476

# IfcWallStandardCase: GENÉRICO - VEDAÇÃO EXTERNA 190 (8)
In: Segundo Pavimento
Type - PredefinedType: STANDARD; Material: GENÉRICO - VEDAÇÃO EXTERNA 190 mm
Classification: Parede (Classificação ARCHICAD); 3E 14 02 00 Parede (NBR 15965-5 3E)
AC_Pset_RenovationAndPhasing - Renovation Status: Existing
ALVENARIAS (Expressão) - Espessura da Argamassa: 10
ArchiCADQuantities - Largura: 190; Espessura: 190; Espessura da Camada de Isolamento: 0; Número de Portas: 0; Número de Furos (Número de Aberturas Vazias): 0; Número de Janelas: 0; Volume dos Pilares: 0; Altura Máxima da Camada da Parede na Face Interna: 0; Altura Mínima da Camada da Parede na Face Interna: 0; Altura Máxima da Camada da Parede na Face Externa: 0; Altura Mínima da Camada da Parede na Face Externa: 0; Espessura da Camada de Ar: 0; Área das Portas: 0; Soma das Larguras das Portas: 0; Espessura do Componente na Face Interna da Parede: 0; Espessura do Componentena na Face Externa da Parede: 0; Área das Janelas: 0; Soma das Larguras das Janelas: 0; Área Analítica da Superfície das Aberturas da Face Interna: 0; Área Analítica da Superfície das Aberturas da Face Externa: 0; Volume Analítico das Aberturas: 0; Espessura da Parede na Terminação: 190; Área de Superfície do Vão na Parede: 0
BaseQuantities - Width: 190
CLASSIFICAÇÕES GERAIS - Transmissão Sonora: 0
SUPERFÍCIES (Mapas) - Superfície da Face (Geral): Pintura - Sienna Areia
Pset_WallCommon - AcousticRating: 0,00
Name | Área = Área da Superfície do Topo (Líquida) = GrossFootprintArea = NetFootprintArea | Altura | Volume (Líquido) = Volume (Condicional) = GrossVolume = NetVolume | Elevação à Origem do Projeto = Elevação ao 1º Nível de Referência = Elevação ao 2º Nível de Referência = Elevação ao Nível do Mar = Elevação da Base Ao Primeiro Nível de Referência = Elevação da Base À Cota Zero = Elevação da Base Ao Nível do Mar = Elevação da Base Ao Segundo Nível de Referência | Elevação ao Piso = Afastamento da Origem = Elevação da Base Ao Piso de Origem | Área da Superfície = Área da Superfície da Base (Líquida) = Área da Superfície da Face Externa da Parede (Líquida) = Área da Superfície da Face Externa da Parede (Condicional) | Comprimento 3D = Comprimento Médio da Parede = Comprimento da Linha de Referência = Comprimento da Face Interna da Parede (Condicional) = Comprimento da Face Externa da Parede (Condicional) = Comprimento da parede no centro = Comprimento da Parede na Face Interna = Comprimento da Parede na Face Externa = Length | Volume (Bruto) | Elevação do Topo ao Primeiro Nível de Referência = Elevação do Topo À Cota Zero = Elevação do Topo Ao Nível do Mar = Elevação do Topo Ao Segundo Nível de Referência | Elevação do Topo Ao Piso de Origem | Afastamento do Topo | Perímetro na Planta | Área da Superfície da Borda (Líquida) = Área da Superfície da Face (Geral) | Número de Pilares | Altura máxima da parede = Height | Altura mínima da parede | Área da Superfície da Face Interna da Parede (Líquida) = Área da Superfície da Face Interna da Parede (Condicional) | Área da Superfície da Face Interna da Parede (Bruta) = Área da Superfície da Face Externa da Parede (Bruta) | GrossSideArea = NetSideArea | ID Dinâmico por Classificação | IsExternal
CIRC2-PAREDE-020 | 0.456 | 2350 | 1.0716 | 2500 | -150 | 5.64 | 2400 | 1.0716 | 4850 | 2200 | -450 | 5180 | 1.805 | 0 | 2350 | 2350 | 5.64 | 5.64 | 5.64 | Parede -020 | yes
CIRC2-PAREDE-026 | 1.30675 | 2470 | 2.95256 | 2650 | 0 | 19.1577 | 7825 | 3.73079 | 5120 | 2470 | -180 | 16030 | 2.01255 | 2 | 2470 | 0 | 19.1577 | 19.6358 | 19.1577 | Parede -026 | no
CIRC2-PAREDE-029 | 1.30675 | 2500 | 3.23096 | 2650 | 0 | 19.3735 | 7825 | 3.7754 | 5150 | 2500 | -150 | 16030 | 2.9118 | 2 | 2500 | 0 | 19.3735 | 19.8705 | 19.3735 | Parede -029 | no
CIRC2-PAREDE-021 | 0.456 | 2350 | 1.0716 | 2500 | -150 | 5.64 | 2400 | 1.0716 | 4850 | 2200 | -450 | 5180 | 1.805 | 0 | 2350 | 2350 | 5.64 | 5.64 | 5.64 | Parede -021 | yes
APTO5-PAREDE-013 | 1.34 | 2650 | 3.04204 | 2650 | 0 | 19.784 | 8000 | 4.028 | 5150 | 2500 | 0 | 16380 | 2.2615 | 2 | 2500 | 0 | 20 | 21.2 | 19.892 | Parede -013 | yes
APTO6-PAREDE-013 | 1.34 | 2650 | 3.04204 | 2650 | 0 | 19.784 | 8000 | 4.028 | 5150 | 2500 | 0 | 16380 | 2.2615 | 2 | 2500 | 0 | 20 | 21.2 | 19.892 | Parede -013 | yes
APTO7-PAREDE-013 | 1.34 | 2650 | 3.04204 | 2650 | 0 | 19.784 | 8000 | 4.028 | 5150 | 2500 | 0 | 16380 | 2.2615 | 2 | 2500 | 0 | 20 | 21.2 | 19.892 | Parede -013 | yes
APTO8-PAREDE-013 | 1.34 | 2650 | 3.04204 | 2650 | 0 | 19.784 | 8000 | 4.028 | 5150 | 2500 | 0 | 16380 | 2.2615 | 2 | 2500 | 0 | 20 | 21.2 | 19.892 | Parede -013 | yes

# IfcWallStandardCase: GENÉRICO - VEDAÇÃO EXTERNA 20 (8)
In: Segundo Pavimento
Type - PredefinedType: STANDARD; Material: GENÉRICO - VEDAÇÃO EXTERNA 20 mm
Classification: Parede (Classificação ARCHICAD); 3E 14 02 00 Parede (NBR 15965-5 3E)
AC_Pset_RenovationAndPhasing - Renovation Status: Existing
ALVENARIAS (Expressão) - Espessura da Argamassa: 10
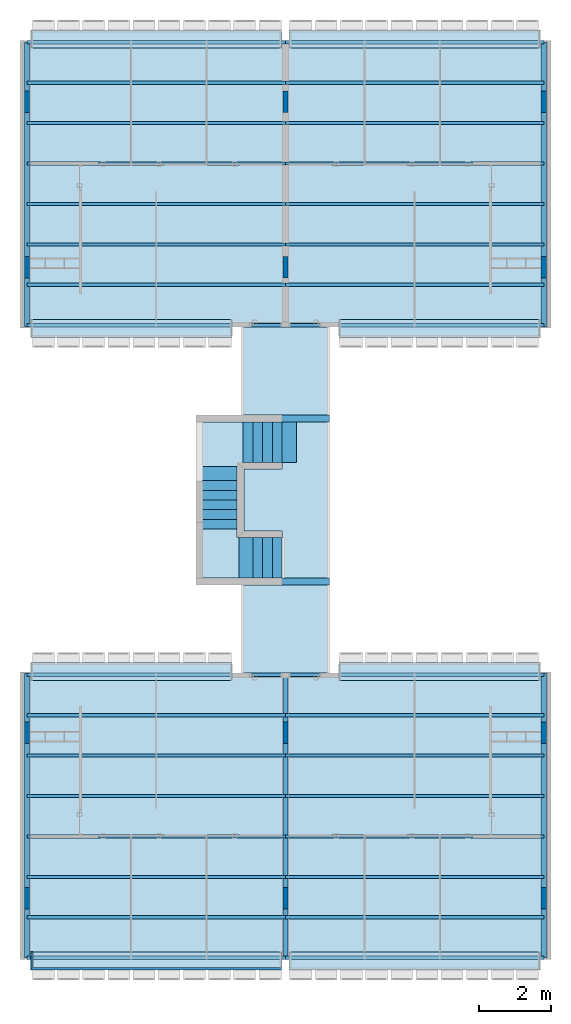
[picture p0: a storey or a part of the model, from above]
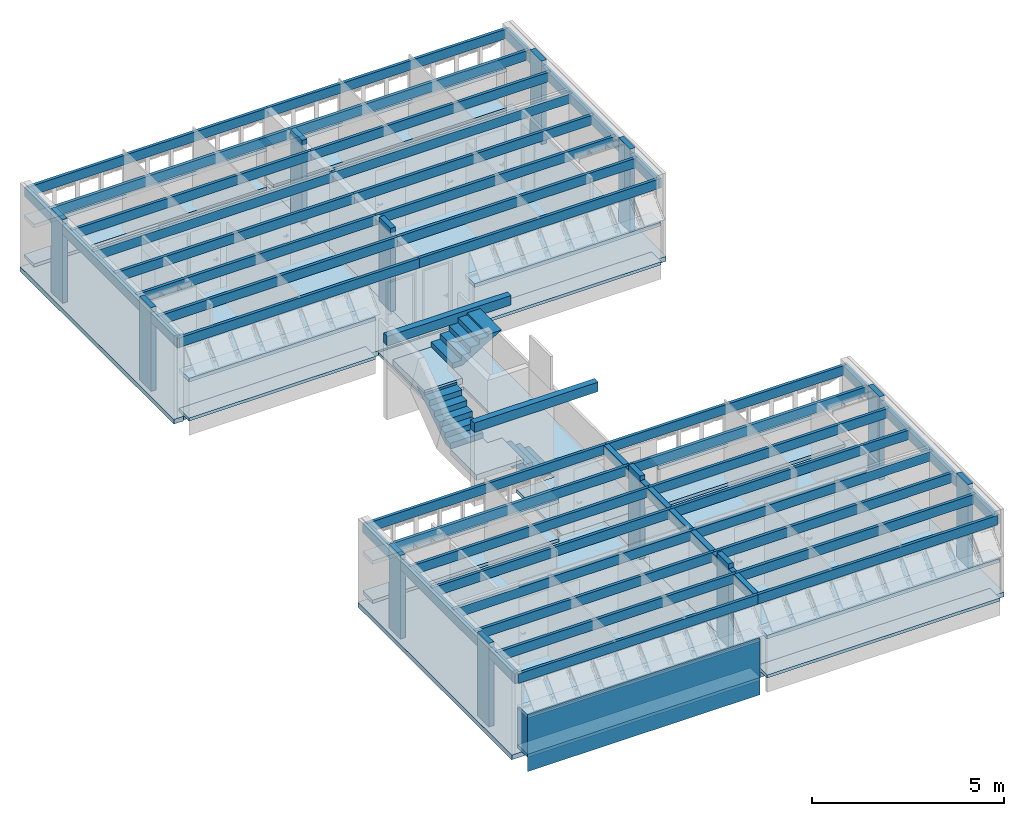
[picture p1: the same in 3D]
Properties of the parts of a building model (IFC2X3), part 3 of 3

# IfcWallStandardCase: GENÉRICO - VEDAÇÃO EXTERNA 20 (8)
ArchiCADQuantities - Área: 0.0044; Altura: 2650; Volume (Líquido): 0.011; Largura: 20; Elevação à Origem do Projeto: 2650; Elevação ao 1º Nível de Referência: 2650; Elevação ao 2º Nível de Referência: 2650; Elevação ao Nível do Mar: 2650; Elevação ao Piso: 0; Afastamento da Origem: 0; Área da Superfície: 0.55; Comprimento 3D: 220; Volume (Condicional): 0.011; Volume (Bruto): 0.0159; Elevação do Topo ao Primeiro Nível de Referência: 5150; Elevação do Topo Ao Piso de Origem: 2500; Elevação do Topo À Cota Zero: 5150; Elevação do Topo Ao Nível do Mar: 5150; Elevação do Topo Ao Segundo Nível de Referência: 5150; Elevação da Base Ao Primeiro Nível de Referência: 2650; Elevação da Base Ao Piso de Origem: 0; Elevação da Base À Cota Zero: 2650; Elevação da Base Ao Nível do Mar: 2650; Elevação da Base Ao Segundo Nível de Referência: 2650; Área da Superfície do Topo (Líquida): 0.0044; Área da Superfície da Base (Líquida): 0.55; Afastamento do Topo: 0; Espessura: 20; Espessura da Camada de Isolamento: 0; Perímetro na Planta: 480; Área da Superfície da Borda (Líquida): 0.0044; Número de Portas: 0; Número de Furos (Número de Aberturas Vazias): 0; Número de Janelas: 0; Número de Pilares: 0; Volume dos Pilares: 0; Altura Máxima da Camada da Parede na Face Interna: 0; Altura Mínima da Camada da Parede na Face Interna: 0; Altura máxima da parede: 2500; Altura mínima da parede: 0; Altura Máxima da Camada da Parede na Face Externa: 0; Altura Mínima da Camada da Parede na Face Externa: 0; Espessura da Camada de Ar: 0; Área das Portas: 0; Soma das Larguras das Portas: 0; Espessura do Componente na Face Interna da Parede: 0; Espessura do Componentena na Face Externa da Parede: 0; Área das Janelas: 0; Soma das Larguras das Janelas: 0; Área Analítica da Superfície das Aberturas da Face Interna: 0; Área Analítica da Superfície das Aberturas da Face Externa: 0; Comprimento Médio da Parede: 220; Área da Superfície da Face Interna da Parede (Líquida): 0.55; Área da Superfície da Face Externa da Parede (Líquida): 0.55; Volume Analítico das Aberturas: 0; Comprimento da Linha de Referência: 300; Comprimento da Face Interna da Parede (Condicional): 220; Área da Superfície da Face Interna da Parede (Condicional): 0.55; Comprimento da Face Externa da Parede (Condicional): 220; Área da Superfície da Face Externa da Parede (Condicional): 0.55; Área da Superfície da Face Interna da Parede (Bruta): 0.795; Área da Superfície da Face Externa da Parede (Bruta): 0.795; Espessura da Parede na Terminação: 20; Comprimento da parede no centro: 220; Comprimento da Parede na Face Interna: 220; Comprimento da Parede na Face Externa: 220; Área de Superfície do Vão na Parede: 0
BaseQuantities - Length: 220; Width: 20; GrossVolume: 0.011; NetVolume: 0.011; Height: 2500; GrossFootprintArea: 0.0044; NetFootprintArea: 0.0044; GrossSideArea: 0.55; NetSideArea: 0.55
CLASSIFICAÇÕES GERAIS - Transmissão Sonora: 0
SUPERFÍCIES (Mapas) - Superfície da Face (Geral): Pintura - Sienna Areia; Área da Superfície da Face (Geral): 0.0044
Pset_WallCommon - AcousticRating: 0,00; IsExternal: no
Name | ID Dinâmico por Classificação
APTO5-PAREDE-009 | Parede -009
APTO5-PAREDE-008 | Parede -008
APTO6-PAREDE-009 | Parede -009
APTO6-PAREDE-008 | Parede -008
APTO7-PAREDE-009 | Parede -009
APTO7-PAREDE-008 | Parede -008
APTO8-PAREDE-009 | Parede -009
APTO8-PAREDE-008 | Parede -008

# IfcWallStandardCase: GENÉRICO - VEDAÇÃO EXTERNA 40 (24)
In: Segundo Pavimento
Type - PredefinedType: STANDARD; Material: GENÉRICO - VEDAÇÃO EXTERNA 40 mm
Classification: Parede (Classificação ARCHICAD); 3E 14 02 00 Parede (NBR 15965-5 3E)
AC_Pset_RenovationAndPhasing - Renovation Status: Existing
ALVENARIAS (Expressão) - Espessura da Argamassa: 10
ArchiCADQuantities - Largura: 40; Elevação à Origem do Projeto: 2650; Elevação ao 1º Nível de Referência: 2650; Elevação ao 2º Nível de Referência: 2650; Elevação ao Nível do Mar: 2650; Elevação ao Piso: 0; Afastamento da Origem: 0; Elevação da Base Ao Primeiro Nível de Referência: 2650; Elevação da Base Ao Piso de Origem: 0; Elevação da Base À Cota Zero: 2650; Elevação da Base Ao Nível do Mar: 2650; Elevação da Base Ao Segundo Nível de Referência: 2650; Espessura: 40; Espessura da Camada de Isolamento: 0; Número de Furos (Número de Aberturas Vazias): 0; Número de Janelas: 0; Número de Pilares: 0; Volume dos Pilares: 0; Altura Máxima da Camada da Parede na Face Interna: 0; Altura Mínima da Camada da Parede na Face Interna: 0; Altura Máxima da Camada da Parede na Face Externa: 0; Altura Mínima da Camada da Parede na Face Externa: 0; Espessura da Camada de Ar: 0; Espessura do Componente na Face Interna da Parede: 0; Espessura do Componentena na Face Externa da Parede: 0; Área das Janelas: 0; Soma das Larguras das Janelas: 0; Espessura da Parede na Terminação: 40; Área de Superfície do Vão na Parede: 0
BaseQuantities - Width: 40
CLASSIFICAÇÕES GERAIS - Transmissão Sonora: 0
SUPERFÍCIES (Mapas) - Superfície da Face (Geral): Pintura - Sienna Areia
Pset_WallCommon - AcousticRating: 0,00; IsExternal: no
Name | Área = Área da Superfície do Topo (Líquida) = GrossFootprintArea = NetFootprintArea | Altura | Volume (Líquido) = NetVolume | Área da Superfície = Área da Superfície da Base (Líquida) = Área da Superfície da Face Interna da Parede (Líquida) = Área da Superfície da Face Externa da Parede (Líquida) = NetSideArea | Comprimento 3D = Comprimento Médio da Parede = Comprimento da parede no centro = Comprimento da Parede na Face Interna = Comprimento da Parede na Face Externa = Length | Volume (Condicional) = GrossVolume | Volume (Bruto) | Elevação do Topo ao Primeiro Nível de Referência = Elevação do Topo À Cota Zero = Elevação do Topo Ao Nível do Mar = Elevação do Topo Ao Segundo Nível de Referência | Elevação do Topo Ao Piso de Origem = Altura máxima da parede = Height | Afastamento do Topo | Perímetro na Planta | Área da Superfície da Borda (Líquida) = Área da Superfície da Face (Geral) | Número de Portas | Altura mínima da parede | Área das Portas = Área Analítica da Superfície das Aberturas da Face Interna = Área Analítica da Superfície das Aberturas da Face Externa | Soma das Larguras das Portas | Volume Analítico das Aberturas | Comprimento da Linha de Referência | Comprimento da Face Interna da Parede (Condicional) = Comprimento da Face Externa da Parede (Condicional) | Área da Superfície da Face Interna da Parede (Condicional) = Área da Superfície da Face Externa da Parede (Condicional) = GrossSideArea | Área da Superfície da Face Interna da Parede (Bruta) = Área da Superfície da Face Externa da Parede (Bruta) | ID Dinâmico por Classificação
APTO5-PAREDE-006 | 0.0968 | 2650 | 0.22376 | 5.594 | 5120 | 0.45056 | 0.54272 | 4850 | 2200 | 0 | 10320 | 0.1888 | 3 | 2200 | 5.67 | 2700 | 0.2268 | 5120 | 2420 | 11.264 | 13.568 | Parede -006
APTO5-PAREDE-007 | 0.1386 | 2650 | 0.340335 | 8.50837 | 3465 | 0.340335 | 0.36729 | 5150 | 2500 | 0 | 7010 | 0.2974 | 0 | 3.55271e-12 | 0 | 0 | 0 | 3465 | 3465 | 8.50837 | 9.18225 | Parede -007
APTO5-PAREDE-003 | 0.15 | 2620 | 0.36904 | 9.226 | 3750 | 0.36904 | 0.393 | 5150 | 2500 | -30 | 7580 | 0.3212 | 0 | 3.55271e-12 | 0 | 0 | 0 | 3750 | 3750 | 9.226 | 9.825 | Parede -003
APTO5-PAREDE-011 | 0.054 | 2650 | 0.135 | 3.375 | 1350 | 0.135 | 0.17278 | 5150 | 2500 | 0 | 2780 | 0.054 | 0 | 0 | 0 | 0 | 0 | 1440 | 1350 | 3.375 | 4.3195 | Parede -011
APTO5-PAREDE-005 | 0.1386 | 2620 | 0.340335 | 8.50837 | 3465 | 0.340335 | 0.363132 | 5150 | 2500 | -30 | 7010 | 0.2974 | 0 | 3.55271e-12 | 0 | 0 | 0 | 3465 | 3465 | 8.50837 | 9.0783 | Parede -005
APTO5-PAREDE-010 | 0.054 | 2650 | 0.135 | 3.375 | 1350 | 0.135 | 0.17278 | 5150 | 2500 | 0 | 2780 | 0.054 | 0 | 0 | 0 | 0 | 0 | 1440 | 1350 | 3.375 | 4.3195 | Parede -010
APTO6-PAREDE-003 | 0.15 | 2620 | 0.36904 | 9.226 | 3750 | 0.36904 | 0.393 | 5150 | 2500 | -30 | 7580 | 0.3212 | 0 | 3.55271e-12 | 0 | 0 | 0 | 3750 | 3750 | 9.226 | 9.825 | Parede -003
APTO6-PAREDE-011 | 0.054 | 2650 | 0.135 | 3.375 | 1350 | 0.135 | 0.17278 | 5150 | 2500 | 0 | 2780 | 0.054 | 0 | 0 | 0 | 0 | 0 | 1440 | 1350 | 3.375 | 4.3195 | Parede -011
APTO6-PAREDE-005 | 0.1386 | 2620 | 0.340335 | 8.50837 | 3465 | 0.340335 | 0.363132 | 5150 | 2500 | -30 | 7010 | 0.2974 | 0 | 3.55271e-12 | 0 | 0 | 0 | 3465 | 3465 | 8.50837 | 9.0783 | Parede -005
APTO6-PAREDE-010 | 0.054 | 2650 | 0.135 | 3.375 | 1350 | 0.135 | 0.17278 | 5150 | 2500 | 0 | 2780 | 0.054 | 0 | 0 | 0 | 0 | 0 | 1440 | 1350 | 3.375 | 4.3195 | Parede -010
APTO6-PAREDE-007 | 0.1386 | 2650 | 0.340335 | 8.50837 | 3465 | 0.340335 | 0.36729 | 5150 | 2500 | 0 | 7010 | 0.2974 | 0 | 3.55271e-12 | 0 | 0 | 0 | 3465 | 3465 | 8.50837 | 9.18225 | Parede -007
APTO6-PAREDE-006 | 0.0968001 | 2650 | 0.22376 | 5.594 | 5120 | 0.45056 | 0.561492 | 4850 | 2200 | 0 | 10320 | 0.1008 | 3 | 0 | 5.67 | 2700 | 0.2268 | 5120 | 2420 | 11.264 | 14.0373 | Parede -006
APTO7-PAREDE-003 | 0.15 | 2620 | 0.36904 | 9.226 | 3750 | 0.36904 | 0.393 | 5150 | 2500 | -30 | 7580 | 0.3212 | 0 | 3.55271e-12 | 0 | 0 | 0 | 3750 | 3750 | 9.226 | 9.825 | Parede -003
APTO7-PAREDE-011 | 0.054 | 2650 | 0.135 | 3.375 | 1350 | 0.135 | 0.17278 | 5150 | 2500 | 0 | 2780 | 0.054 | 0 | 0 | 0 | 0 | 0 | 1440 | 1350 | 3.375 | 4.3195 | Parede -011
APTO7-PAREDE-005 | 0.1386 | 2620 | 0.340335 | 8.50837 | 3465 | 0.340335 | 0.363132 | 5150 | 2500 | -30 | 7010 | 0.2974 | 0 | 3.55271e-12 | 0 | 0 | 0 | 3465 | 3465 | 8.50837 | 9.0783 | Parede -005
APTO7-PAREDE-010 | 0.054 | 2650 | 0.135 | 3.375 | 1350 | 0.135 | 0.17278 | 5150 | 2500 | 0 | 2780 | 0.054 | 0 | 0 | 0 | 0 | 0 | 1440 | 1350 | 3.375 | 4.3195 | Parede -010
APTO7-PAREDE-007 | 0.1386 | 2650 | 0.340335 | 8.50837 | 3465 | 0.340335 | 0.36729 | 5150 | 2500 | 0 | 7010 | 0.2974 | 0 | 3.55271e-12 | 0 | 0 | 0 | 3465 | 3465 | 8.50837 | 9.18225 | Parede -007
APTO7-PAREDE-006 | 0.0968 | 2650 | 0.22376 | 5.594 | 5120 | 0.45056 | 0.54272 | 4850 | 2200 | 0 | 10320 | 0.1888 | 3 | 2200 | 5.67 | 2700 | 0.2268 | 5120 | 2420 | 11.264 | 13.568 | Parede -006
APTO8-PAREDE-003 | 0.15 | 2620 | 0.36904 | 9.226 | 3750 | 0.36904 | 0.393 | 5150 | 2500 | -30 | 7580 | 0.3212 | 0 | 3.55271e-12 | 0 | 0 | 0 | 3750 | 3750 | 9.226 | 9.825 | Parede -003
APTO8-PAREDE-011 | 0.054 | 2650 | 0.135 | 3.375 | 1350 | 0.135 | 0.17278 | 5150 | 2500 | 0 | 2780 | 0.054 | 0 | 0 | 0 | 0 | 0 | 1440 | 1350 | 3.375 | 4.3195 | Parede -011
APTO8-PAREDE-005 | 0.1386 | 2620 | 0.340335 | 8.50837 | 3465 | 0.340335 | 0.363132 | 5150 | 2500 | -30 | 7010 | 0.2974 | 0 | 3.55271e-12 | 0 | 0 | 0 | 3465 | 3465 | 8.50837 | 9.0783 | Parede -005
APTO8-PAREDE-010 | 0.054 | 2650 | 0.135 | 3.375 | 1350 | 0.135 | 0.17278 | 5150 | 2500 | 0 | 2780 | 0.054 | 0 | 0 | 0 | 0 | 0 | 1440 | 1350 | 3.375 | 4.3195 | Parede -010
APTO8-PAREDE-007 | 0.1386 | 2650 | 0.340335 | 8.50837 | 3465 | 0.340335 | 0.36729 | 5150 | 2500 | 0 | 7010 | 0.2974 | 0 | 3.55271e-12 | 0 | 0 | 0 | 3465 | 3465 | 8.50837 | 9.18225 | Parede -007
APTO8-PAREDE-006 | 0.0968001 | 2650 | 0.22376 | 5.594 | 5120 | 0.45056 | 0.56172 | 4850 | 2200 | 0 | 10320 | 0.1008 | 3 | 0 | 5.67 | 2700 | 0.2268 | 5120 | 2420 | 11.264 | 14.043 | Parede -006

# IfcWallStandardCase: GENÉRICO - VEDAÇÃO EXTERNA 75 (4)
In: Segundo Pavimento
Type - PredefinedType: STANDARD; Material: GENÉRICO - VEDAÇÃO EXTERNA 75 mm
Classification: Parede (Classificação ARCHICAD); 3E 08 04 10 Guarda-corpo (NBR 15965-5 3E)
AC_Pset_RenovationAndPhasing - Renovation Status: Existing
ALVENARIAS (Expressão) - Espessura da Argamassa: 10
ArchiCADQuantities - Altura: 1050; Largura: 75; Espessura: 75; Espessura da Camada de Isolamento: 0; Número de Portas: 0; Número de Furos (Número de Aberturas Vazias): 0; Número de Janelas: 0; Número de Pilares: 0; Volume dos Pilares: 0; Altura Máxima da Camada da Parede na Face Interna: 0; Altura Mínima da Camada da Parede na Face Interna: 0; Altura máxima da parede: 1050; Altura Máxima da Camada da Parede na Face Externa: 0; Altura Mínima da Camada da Parede na Face Externa: 0; Espessura da Camada de Ar: 0; Área das Portas: 0; Soma das Larguras das Portas: 0; Espessura do Componente na Face Interna da Parede: 0; Espessura do Componentena na Face Externa da Parede: 0; Área das Janelas: 0; Soma das Larguras das Janelas: 0; Área Analítica da Superfície das Aberturas da Face Interna: 0; Área Analítica da Superfície das Aberturas da Face Externa: 0; Volume Analítico das Aberturas: 0; Espessura da Parede na Terminação: 75; Área de Superfície do Vão na Parede: 0
BaseQuantities - Width: 75; Height: 1050
CLASSIFICAÇÕES GERAIS - Transmissão Sonora: 0
SUPERFÍCIES (Mapas) - Superfície da Face (Geral): Pintura - Sienna Areia
Pset_WallCommon - AcousticRating: 0,00; IsExternal: yes
Name | Área = Área da Superfície do Topo (Líquida) = GrossFootprintArea = NetFootprintArea | Volume (Líquido) = Volume (Condicional) = GrossVolume = NetVolume | Elevação à Origem do Projeto = Elevação ao 1º Nível de Referência = Elevação ao 2º Nível de Referência = Elevação ao Nível do Mar = Elevação da Base Ao Primeiro Nível de Referência = Elevação da Base À Cota Zero = Elevação da Base Ao Nível do Mar = Elevação da Base Ao Segundo Nível de Referência | Elevação ao Piso = Afastamento da Origem = Elevação da Base Ao Piso de Origem | Área da Superfície = Área da Superfície da Base (Líquida) = Área da Superfície da Face Interna da Parede (Líquida) = Área da Superfície da Face Externa da Parede (Líquida) = Área da Superfície da Face Interna da Parede (Condicional) = Área da Superfície da Face Externa da Parede (Condicional) = GrossSideArea = NetSideArea | Comprimento 3D = Comprimento Médio da Parede = Comprimento da Linha de Referência = Comprimento da Face Interna da Parede (Condicional) = Comprimento da Face Externa da Parede (Condicional) = Comprimento da parede no centro = Comprimento da Parede na Face Interna = Comprimento da Parede na Face Externa = Length | Volume (Bruto) | Elevação do Topo ao Primeiro Nível de Referência = Elevação do Topo À Cota Zero = Elevação do Topo Ao Nível do Mar = Elevação do Topo Ao Segundo Nível de Referência | Elevação do Topo Ao Piso de Origem | Afastamento do Topo | Perímetro na Planta | Área da Superfície da Borda (Líquida) = Área da Superfície da Face (Geral) | Altura mínima da parede | Área da Superfície da Face Interna da Parede (Bruta) = Área da Superfície da Face Externa da Parede (Bruta) | ID Dinâmico por Classificação
PAREDE-040 | 0.084 | 0.0882 | 5250 | 2600 | 1.176 | 1120 | 0.103163 | 6300 | 3650 | 0 | 2390 | 0.24675 | 0 | 1.3755 | Parede -040
CIRC2-PAREDE-027 | 0.72225 | 0.758363 | 2600 | -50 | 10.1115 | 9630 | 0.758363 | 3650 | 1000 | -1650 | 19410 | 1.602 | 1050 | 10.1115 | Parede -027
CIRC2-PAREDE-028 | 0.184125 | 0.193331 | 2600 | -50 | 2.57775 | 2455 | 0.208294 | 3650 | 1000 | -1650 | 5060 | 0.447 | 0 | 2.77725 | Parede -028
CIRC2-PAREDE-025 | 0.184125 | 0.193331 | 2600 | -50 | 2.57775 | 2455 | 0.193331 | 3650 | 1000 | -1650 | 5060 | 0.52575 | 1050 | 2.57775 | Parede -025

# IfcWallStandardCase: GENÉRICO - VEDAÇÃO EXTERNA 90 (12)
In: Segundo Pavimento
Type - PredefinedType: STANDARD; Material: GENÉRICO - VEDAÇÃO EXTERNA 90 mm
Classification: Parede (Classificação ARCHICAD); 3E 14 02 00 Parede (NBR 15965-5 3E)
AC_Pset_RenovationAndPhasing - Renovation Status: Existing
ALVENARIAS (Expressão) - Espessura da Argamassa: 10
ArchiCADQuantities - Largura: 90; Elevação à Origem do Projeto: 2650; Elevação ao 1º Nível de Referência: 2650; Elevação ao 2º Nível de Referência: 2650; Elevação ao Nível do Mar: 2650; Elevação ao Piso: 0; Afastamento da Origem: 0; Elevação da Base Ao Primeiro Nível de Referência: 2650; Elevação da Base Ao Piso de Origem: 0; Elevação da Base À Cota Zero: 2650; Elevação da Base Ao Nível do Mar: 2650; Elevação da Base Ao Segundo Nível de Referência: 2650; Espessura: 90; Espessura da Camada de Isolamento: 0; Número de Furos (Número de Aberturas Vazias): 0; Número de Janelas: 0; Número de Pilares: 0; Volume dos Pilares: 0; Altura Máxima da Camada da Parede na Face Interna: 0; Altura Mínima da Camada da Parede na Face Interna: 0; Altura Máxima da Camada da Parede na Face Externa: 0; Altura Mínima da Camada da Parede na Face Externa: 0; Espessura da Camada de Ar: 0; Espessura do Componente na Face Interna da Parede: 0; Espessura do Componentena na Face Externa da Parede: 0; Área das Janelas: 0; Soma das Larguras das Janelas: 0; Espessura da Parede na Terminação: 90; Área de Superfície do Vão na Parede: 0
BaseQuantities - Width: 90
CLASSIFICAÇÕES GERAIS - Transmissão Sonora: 0
SUPERFÍCIES (Mapas) - Superfície da Face (Geral): Pintura - Sienna Areia
Pset_WallCommon - AcousticRating: 0,00
Name | Área = Área da Superfície do Topo (Líquida) = GrossFootprintArea = NetFootprintArea | Altura | Volume (Líquido) = NetVolume | Área da Superfície = Área da Superfície da Base (Líquida) = Área da Superfície da Face Interna da Parede (Líquida) = Área da Superfície da Face Externa da Parede (Líquida) = NetSideArea | Comprimento 3D = Comprimento Médio da Parede = Comprimento da Linha de Referência = Comprimento da parede no centro = Comprimento da Parede na Face Interna = Comprimento da Parede na Face Externa = Length | Volume (Condicional) = GrossVolume | Volume (Bruto) | Elevação do Topo ao Primeiro Nível de Referência = Elevação do Topo À Cota Zero = Elevação do Topo Ao Nível do Mar = Elevação do Topo Ao Segundo Nível de Referência | Elevação do Topo Ao Piso de Origem = Altura máxima da parede = Height | Afastamento do Topo | Perímetro na Planta | Área da Superfície da Borda (Líquida) = Área da Superfície da Face (Geral) | Número de Portas | Altura mínima da parede | Área das Portas = Área Analítica da Superfície das Aberturas da Face Interna = Área Analítica da Superfície das Aberturas da Face Externa | Soma das Larguras das Portas | Volume Analítico das Aberturas | Comprimento da Face Interna da Parede (Condicional) = Comprimento da Face Externa da Parede (Condicional) | Área da Superfície da Face Interna da Parede (Condicional) = Área da Superfície da Face Externa da Parede (Condicional) = GrossSideArea | Área da Superfície da Face Interna da Parede (Bruta) = Área da Superfície da Face Externa da Parede (Bruta) | ID Dinâmico por Classificação | IsExternal
APTO5-PAREDE-019 | 0.1692 | 2650 | 0.37224 | 4.136 | 1880 | 0.37224 | 0.493695 | 4850 | 2200 | 0 | 3940 | 0.3672 | 0 | 0 | 0 | 0 | 0 | 1880 | 4.136 | 5.4855 | Parede -019 | no
APTO5-PAREDE-014 | 0.72 | 2650 | 1.8 | 20 | 8000 | 1.8 | 1.908 | 5150 | 2500 | 0 | 16180 | 1.17 | 0 | 2500 | 0 | 0 | 0 | 8000 | 20 | 21.2 | Parede -014 | yes
APTO5-PAREDE-012 | 0.2583 | 2500 | 0.66402 | 7.378 | 3580 | 0.79821 | 0.82575 | 5150 | 2500 | -150 | 7340 | 0.7812 | 1 | 2100 | 1.491 | 710 | 0.13419 | 2870 | 8.869 | 9.175 | Parede -012 | no
APTO6-PAREDE-019 | 0.1692 | 2650 | 0.37224 | 4.136 | 1880 | 0.37224 | 0.493695 | 4850 | 2200 | 0 | 3940 | 0.3672 | 0 | 0 | 0 | 0 | 0 | 1880 | 4.136 | 5.4855 | Parede -019 | no
APTO6-PAREDE-014 | 0.72 | 2650 | 1.8 | 20 | 8000 | 1.8 | 1.908 | 5150 | 2500 | 0 | 16180 | 1.17 | 0 | 2500 | 0 | 0 | 0 | 8000 | 20 | 21.2 | Parede -014 | yes
APTO6-PAREDE-012 | 0.2583 | 2500 | 0.66402 | 7.378 | 3580 | 0.79821 | 0.82575 | 5150 | 2500 | -150 | 7340 | 0.7812 | 1 | 2100 | 1.491 | 710 | 0.13419 | 2870 | 8.869 | 9.175 | Parede -012 | no
APTO7-PAREDE-019 | 0.1692 | 2650 | 0.37224 | 4.136 | 1880 | 0.37224 | 0.493695 | 4850 | 2200 | 0 | 3940 | 0.3672 | 0 | 0 | 0 | 0 | 0 | 1880 | 4.136 | 5.4855 | Parede -019 | no
APTO7-PAREDE-014 | 0.72 | 2650 | 1.8 | 20 | 8000 | 1.8 | 1.908 | 5150 | 2500 | 0 | 16180 | 1.17 | 0 | 2500 | 0 | 0 | 0 | 8000 | 20 | 21.2 | Parede -014 | yes
APTO7-PAREDE-012 | 0.2583 | 2500 | 0.66402 | 7.378 | 3580 | 0.79821 | 0.82575 | 5150 | 2500 | -150 | 7340 | 0.7812 | 1 | 2100 | 1.491 | 710 | 0.13419 | 2870 | 8.869 | 9.175 | Parede -012 | no
APTO8-PAREDE-019 | 0.1692 | 2650 | 0.37224 | 4.136 | 1880 | 0.37224 | 0.493695 | 4850 | 2200 | 0 | 3940 | 0.3672 | 0 | 0 | 0 | 0 | 0 | 1880 | 4.136 | 5.4855 | Parede -019 | no
APTO8-PAREDE-014 | 0.72 | 2650 | 1.8 | 20 | 8000 | 1.8 | 1.908 | 5150 | 2500 | 0 | 16180 | 1.17 | 0 | 2500 | 0 | 0 | 0 | 8000 | 20 | 21.2 | Parede -014 | yes
APTO8-PAREDE-012 | 0.2583 | 2500 | 0.66402 | 7.378 | 3580 | 0.79821 | 0.82575 | 5150 | 2500 | -150 | 7340 | 0.7812 | 1 | 2100 | 1.491 | 710 | 0.13419 | 2870 | 8.869 | 9.175 | Parede -012 | no

# IfcWindow (8)
In: Segundo Pavimento
Type - ParameterTakesPrecedence: no; Sizeable: no
Classification: Janela (Classificação ARCHICAD); 3E 20 04 02 06 Janela basculante (NBR 15965-5 3E)
AC_Pset_RenovationAndPhasing - Renovation Status: Existing
ArchiCADQuantities - Altura: 845; Espessura: 50; Comprimento Total das Estruturas Pertencentes ao Eixo Secundário: 0; Comprimento Total da Estrutura Personalizada: 0; Área Total da Superfície dos painéis de revestimento Leste: 0; Área Total dos Painéis de Revestimento Oeste: 0; Área Total da Superfície dos painéis de revestimento Nordeste: 0; Área Total dos Painéis de Revestimento Noroeste: 0; Área Total da Superfície dos painéis de revestimento Sudeste: 0; Área Total dos Painéis de Revestimento Sudoeste: 0
BaseQuantities - Width: 50; Height: 845
EXPRESSÕES DE TEXTO (Expressão) - Localização do Produto no Projeto: Projeto: CECAP GuarulhosLocal: Piso: Segundo Pavimento Cômodo:
FABRICAÇÃO - Data de Fabricação: DD/MM/YYYY; Site do Produto: www.graphisoft.com
GARANTIA - Ínicio da Garantia: DD/MM/YYYY; Fim da Garantia: DD/MM/YYYY
INFORMAÇÕES DO PRODUTO - Data de Aquisição: DD/MM/YYYY
Pset_ManufacturerTypeInformation - ProductionYear: DD/MM/YYYY
Pset_WindowCommon - IsExternal: yes
Name | Elevação à Origem do Projeto = Elevação ao 1º Nível de Referência = Elevação ao 2º Nível de Referência = Elevação ao Nível do Mar = Elevação da Base Ao Primeiro Nível de Referência = Elevação da Base À Cota Zero = Elevação da Base Ao Nível do Mar = Elevação da Base Ao Segundo Nível de Referência | Elevação ao Piso = Afastamento da Origem = Elevação da Base Ao Piso de Origem | Área da Superfície = Área da Superfície da Base (Líquida) = Área de Superfície Incluindo Contorno = GrossArea = Area | Elevação do Topo ao Primeiro Nível de Referência = Elevação do Topo À Cota Zero = Elevação do Topo Ao Nível do Mar = Elevação do Topo Ao Segundo Nível de Referência | Elevação do Topo Ao Piso de Origem | Número de Paineis | Comprimento de Estruturas Total | Área Total da Superfície de Painel | Comprimento | Comprimento Total do Contorno da Estrutura | Comprimento Total das Estruturas Pertencentes ao Eixo Principal | Área Total dos Painéis de Revestimento Norte | Área Total dos Painéis de Revestimento Sul | NetVolume | ID Dinâmico por Classificação | ID de Aberturas com Master ID
APTO5-JANELA-001 | 4005.02 | 1355.02 | 5.915 | 4850.02 | 2200.02 | 11 | 24140 | 5.50517 | 7000 | 15690 | 8450 | 0 | 5.50517 | 0.29575 | Janela -001 | APTO5-001
APTO5-JANELA-000 | 4005 | 1355 | 4.74045 | 4850 | 2200 | 9 | 19670 | 4.41512 | 5610 | 12910 | 6760 | 4.41512 | 0 | 0.237023 | Janela -000 | APTO5-000
APTO6-JANELA-000 | 4005 | 1355 | 4.74045 | 4850 | 2200 | 9 | 19670 | 4.41512 | 5610 | 12910 | 6760 | 4.41512 | 0 | 0.237023 | Janela -000 | APTO6-000
APTO6-JANELA-001 | 4005.02 | 1355.02 | 5.915 | 4850.02 | 2200.02 | 11 | 24140 | 5.50517 | 7000 | 15690 | 8450 | 0 | 5.50517 | 0.29575 | Janela -001 | APTO6-001
APTO7-JANELA-000 | 4005 | 1355 | 4.74045 | 4850 | 2200 | 9 | 19670 | 4.41512 | 5610 | 12910 | 6760 | 0 | 4.41512 | 0.237023 | Janela -000 | APTO7-000
APTO7-JANELA-001 | 4005.02 | 1355.02 | 5.915 | 4850.02 | 2200.02 | 11 | 24140 | 5.50517 | 7000 | 15690 | 8450 | 5.50517 | 0 | 0.29575 | Janela -001 | APTO7-001
APTO8-JANELA-000 | 4005 | 1355 | 4.74045 | 4850 | 2200 | 9 | 19670 | 4.41512 | 5610 | 12910 | 6760 | 0 | 4.41512 | 0.237023 | Janela -000 | APTO8-000
APTO8-JANELA-001 | 4005.02 | 1355.02 | 5.915 | 4850.02 | 2200.02 | 11 | 24140 | 5.50517 | 7000 | 15690 | 8450 | 5.50517 | 0 | 0.29575 | Janela -001 | APTO8-001
